VERSION 5.4 ;
NAMESCASESENSITIVE ON ;
BUSBITCHARS "[]" ;
DIVIDERCHAR "/" ;
UNITS
  DATABASE MICRONS 2000 ;
END UNITS
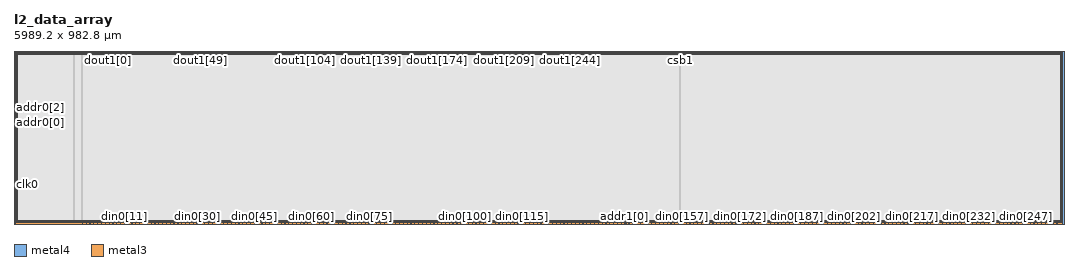
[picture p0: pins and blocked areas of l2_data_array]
MACRO l2_data_array
   CLASS BLOCK ;
   SIZE 5989.2 BY 982.8 ;
   SYMMETRY X Y R90 ;
   PIN din0[0]
      DIRECTION INPUT ;
      PORT
         LAYER metal4 ;
         RECT  389.4 0.0 390.6 1.2 ;
      END
   END din0[0]
   PIN din0[1]
      DIRECTION INPUT ;
      PORT
         LAYER metal4 ;
         RECT  411.2 0.0 412.4 1.2 ;
      END
   END din0[1]
   PIN din0[2]
      DIRECTION INPUT ;
      PORT
         LAYER metal4 ;
         RECT  433.0 0.0 434.2 1.2 ;
      END
   END din0[2]
   PIN din0[3]
      DIRECTION INPUT ;
      PORT
         LAYER metal4 ;
         RECT  454.8 0.0 456.0 1.2 ;
      END
   END din0[3]
   PIN din0[4]
      DIRECTION INPUT ;
      PORT
         LAYER metal4 ;
         RECT  476.6 0.0 477.8 1.2 ;
      END
   END din0[4]
   PIN din0[5]
      DIRECTION INPUT ;
      PORT
         LAYER metal4 ;
         RECT  498.4 0.0 499.6 1.2 ;
      END
   END din0[5]
   PIN din0[6]
      DIRECTION INPUT ;
      PORT
         LAYER metal4 ;
         RECT  520.2 0.0 521.4 1.2 ;
      END
   END din0[6]
   PIN din0[7]
      DIRECTION INPUT ;
      PORT
         LAYER metal4 ;
         RECT  542.0 0.0 543.2 1.2 ;
      END
   END din0[7]
   PIN din0[8]
      DIRECTION INPUT ;
      PORT
         LAYER metal4 ;
         RECT  563.8 0.0 565.0 1.2 ;
      END
   END din0[8]
   PIN din0[9]
      DIRECTION INPUT ;
      PORT
         LAYER metal4 ;
         RECT  585.6 0.0 586.8 1.2 ;
      END
   END din0[9]
   PIN din0[10]
      DIRECTION INPUT ;
      PORT
         LAYER metal4 ;
         RECT  607.4 0.0 608.6 1.2 ;
      END
   END din0[10]
   PIN din0[11]
      DIRECTION INPUT ;
      PORT
         LAYER metal4 ;
         RECT  629.2 0.0 630.4 1.2 ;
      END
   END din0[11]
   PIN din0[12]
      DIRECTION INPUT ;
      PORT
         LAYER metal4 ;
         RECT  651.0 0.0 652.2 1.2 ;
      END
   END din0[12]
   PIN din0[13]
      DIRECTION INPUT ;
      PORT
         LAYER metal4 ;
         RECT  672.8 0.0 674.0 1.2 ;
      END
   END din0[13]
   PIN din0[14]
      DIRECTION INPUT ;
      PORT
         LAYER metal4 ;
         RECT  694.6 0.0 695.8 1.2 ;
      END
   END din0[14]
   PIN din0[15]
      DIRECTION INPUT ;
      PORT
         LAYER metal4 ;
         RECT  716.4 0.0 717.6 1.2 ;
      END
   END din0[15]
   PIN din0[16]
      DIRECTION INPUT ;
      PORT
         LAYER metal4 ;
         RECT  738.2 0.0 739.4 1.2 ;
      END
   END din0[16]
   PIN din0[17]
      DIRECTION INPUT ;
      PORT
         LAYER metal4 ;
         RECT  760.0 0.0 761.2 1.2 ;
      END
   END din0[17]
   PIN din0[18]
      DIRECTION INPUT ;
      PORT
         LAYER metal4 ;
         RECT  781.8 0.0 783.0 1.2 ;
      END
   END din0[18]
   PIN din0[19]
      DIRECTION INPUT ;
      PORT
         LAYER metal4 ;
         RECT  803.6 0.0 804.8 1.2 ;
      END
   END din0[19]
   PIN din0[20]
      DIRECTION INPUT ;
      PORT
         LAYER metal4 ;
         RECT  825.4 0.0 826.6 1.2 ;
      END
   END din0[20]
   PIN din0[21]
      DIRECTION INPUT ;
      PORT
         LAYER metal4 ;
         RECT  847.2 0.0 848.4 1.2 ;
      END
   END din0[21]
   PIN din0[22]
      DIRECTION INPUT ;
      PORT
         LAYER metal4 ;
         RECT  869.0 0.0 870.2 1.2 ;
      END
   END din0[22]
   PIN din0[23]
      DIRECTION INPUT ;
      PORT
         LAYER metal4 ;
         RECT  890.8 0.0 892.0 1.2 ;
      END
   END din0[23]
   PIN din0[24]
      DIRECTION INPUT ;
      PORT
         LAYER metal4 ;
         RECT  912.6 0.0 913.8 1.2 ;
      END
   END din0[24]
   PIN din0[25]
      DIRECTION INPUT ;
      PORT
         LAYER metal4 ;
         RECT  934.4 0.0 935.6 1.2 ;
      END
   END din0[25]
   PIN din0[26]
      DIRECTION INPUT ;
      PORT
         LAYER metal4 ;
         RECT  956.2 0.0 957.4 1.2 ;
      END
   END din0[26]
   PIN din0[27]
      DIRECTION INPUT ;
      PORT
         LAYER metal4 ;
         RECT  978.0 0.0 979.2 1.2 ;
      END
   END din0[27]
   PIN din0[28]
      DIRECTION INPUT ;
      PORT
         LAYER metal4 ;
         RECT  999.8 0.0 1001.0 1.2 ;
      END
   END din0[28]
   PIN din0[29]
      DIRECTION INPUT ;
      PORT
         LAYER metal4 ;
         RECT  1021.6 0.0 1022.8 1.2 ;
      END
   END din0[29]
   PIN din0[30]
      DIRECTION INPUT ;
      PORT
         LAYER metal4 ;
         RECT  1043.4 0.0 1044.6 1.2 ;
      END
   END din0[30]
   PIN din0[31]
      DIRECTION INPUT ;
      PORT
         LAYER metal4 ;
         RECT  1065.2 0.0 1066.4 1.2 ;
      END
   END din0[31]
   PIN din0[32]
      DIRECTION INPUT ;
      PORT
         LAYER metal4 ;
         RECT  1087.0 0.0 1088.2 1.2 ;
      END
   END din0[32]
   PIN din0[33]
      DIRECTION INPUT ;
      PORT
         LAYER metal4 ;
         RECT  1108.8 0.0 1110.0 1.2 ;
      END
   END din0[33]
   PIN din0[34]
      DIRECTION INPUT ;
      PORT
         LAYER metal4 ;
         RECT  1130.6 0.0 1131.8 1.2 ;
      END
   END din0[34]
   PIN din0[35]
      DIRECTION INPUT ;
      PORT
         LAYER metal4 ;
         RECT  1152.4 0.0 1153.6 1.2 ;
      END
   END din0[35]
   PIN din0[36]
      DIRECTION INPUT ;
      PORT
         LAYER metal4 ;
         RECT  1174.2 0.0 1175.4 1.2 ;
      END
   END din0[36]
   PIN din0[37]
      DIRECTION INPUT ;
      PORT
         LAYER metal4 ;
         RECT  1196.0 0.0 1197.2 1.2 ;
      END
   END din0[37]
   PIN din0[38]
      DIRECTION INPUT ;
      PORT
         LAYER metal4 ;
         RECT  1217.8 0.0 1219.0 1.2 ;
      END
   END din0[38]
   PIN din0[39]
      DIRECTION INPUT ;
      PORT
         LAYER metal4 ;
         RECT  1239.6 0.0 1240.8 1.2 ;
      END
   END din0[39]
   PIN din0[40]
      DIRECTION INPUT ;
      PORT
         LAYER metal4 ;
         RECT  1261.4 0.0 1262.6 1.2 ;
      END
   END din0[40]
   PIN din0[41]
      DIRECTION INPUT ;
      PORT
         LAYER metal4 ;
         RECT  1283.2 0.0 1284.4 1.2 ;
      END
   END din0[41]
   PIN din0[42]
      DIRECTION INPUT ;
      PORT
         LAYER metal4 ;
         RECT  1305.0 0.0 1306.2 1.2 ;
      END
   END din0[42]
   PIN din0[43]
      DIRECTION INPUT ;
      PORT
         LAYER metal4 ;
         RECT  1326.8 0.0 1328.0 1.2 ;
      END
   END din0[43]
   PIN din0[44]
      DIRECTION INPUT ;
      PORT
         LAYER metal4 ;
         RECT  1348.6 0.0 1349.8 1.2 ;
      END
   END din0[44]
   PIN din0[45]
      DIRECTION INPUT ;
      PORT
         LAYER metal4 ;
         RECT  1370.4 0.0 1371.6 1.2 ;
      END
   END din0[45]
   PIN din0[46]
      DIRECTION INPUT ;
      PORT
         LAYER metal4 ;
         RECT  1392.2 0.0 1393.4 1.2 ;
      END
   END din0[46]
   PIN din0[47]
      DIRECTION INPUT ;
      PORT
         LAYER metal4 ;
         RECT  1414.0 0.0 1415.2 1.2 ;
      END
   END din0[47]
   PIN din0[48]
      DIRECTION INPUT ;
      PORT
         LAYER metal4 ;
         RECT  1435.8 0.0 1437.0 1.2 ;
      END
   END din0[48]
   PIN din0[49]
      DIRECTION INPUT ;
      PORT
         LAYER metal4 ;
         RECT  1457.6 0.0 1458.8 1.2 ;
      END
   END din0[49]
   PIN din0[50]
      DIRECTION INPUT ;
      PORT
         LAYER metal4 ;
         RECT  1479.4 0.0 1480.6 1.2 ;
      END
   END din0[50]
   PIN din0[51]
      DIRECTION INPUT ;
      PORT
         LAYER metal4 ;
         RECT  1501.2 0.0 1502.4 1.2 ;
      END
   END din0[51]
   PIN din0[52]
      DIRECTION INPUT ;
      PORT
         LAYER metal4 ;
         RECT  1523.0 0.0 1524.2 1.2 ;
      END
   END din0[52]
   PIN din0[53]
      DIRECTION INPUT ;
      PORT
         LAYER metal4 ;
         RECT  1544.8 0.0 1546.0 1.2 ;
      END
   END din0[53]
   PIN din0[54]
      DIRECTION INPUT ;
      PORT
         LAYER metal4 ;
         RECT  1566.6 0.0 1567.8 1.2 ;
      END
   END din0[54]
   PIN din0[55]
      DIRECTION INPUT ;
      PORT
         LAYER metal4 ;
         RECT  1588.4 0.0 1589.6 1.2 ;
      END
   END din0[55]
   PIN din0[56]
      DIRECTION INPUT ;
      PORT
         LAYER metal4 ;
         RECT  1610.2 0.0 1611.4 1.2 ;
      END
   END din0[56]
   PIN din0[57]
      DIRECTION INPUT ;
      PORT
         LAYER metal4 ;
         RECT  1632.0 0.0 1633.2 1.2 ;
      END
   END din0[57]
   PIN din0[58]
      DIRECTION INPUT ;
      PORT
         LAYER metal4 ;
         RECT  1653.8 0.0 1655.0 1.2 ;
      END
   END din0[58]
   PIN din0[59]
      DIRECTION INPUT ;
      PORT
         LAYER metal4 ;
         RECT  1675.6 0.0 1676.8 1.2 ;
      END
   END din0[59]
   PIN din0[60]
      DIRECTION INPUT ;
      PORT
         LAYER metal4 ;
         RECT  1697.4 0.0 1698.6 1.2 ;
      END
   END din0[60]
   PIN din0[61]
      DIRECTION INPUT ;
      PORT
         LAYER metal4 ;
         RECT  1719.2 0.0 1720.4 1.2 ;
      END
   END din0[61]
   PIN din0[62]
      DIRECTION INPUT ;
      PORT
         LAYER metal4 ;
         RECT  1741.0 0.0 1742.2 1.2 ;
      END
   END din0[62]
   PIN din0[63]
      DIRECTION INPUT ;
      PORT
         LAYER metal4 ;
         RECT  1762.8 0.0 1764.0 1.2 ;
      END
   END din0[63]
   PIN din0[64]
      DIRECTION INPUT ;
      PORT
         LAYER metal4 ;
         RECT  1784.6 0.0 1785.8 1.2 ;
      END
   END din0[64]
   PIN din0[65]
      DIRECTION INPUT ;
      PORT
         LAYER metal4 ;
         RECT  1806.4 0.0 1807.6 1.2 ;
      END
   END din0[65]
   PIN din0[66]
      DIRECTION INPUT ;
      PORT
         LAYER metal4 ;
         RECT  1828.2 0.0 1829.4 1.2 ;
      END
   END din0[66]
   PIN din0[67]
      DIRECTION INPUT ;
      PORT
         LAYER metal4 ;
         RECT  1850.0 0.0 1851.2 1.2 ;
      END
   END din0[67]
   PIN din0[68]
      DIRECTION INPUT ;
      PORT
         LAYER metal4 ;
         RECT  1871.8 0.0 1873.0 1.2 ;
      END
   END din0[68]
   PIN din0[69]
      DIRECTION INPUT ;
      PORT
         LAYER metal4 ;
         RECT  1893.6 0.0 1894.8 1.2 ;
      END
   END din0[69]
   PIN din0[70]
      DIRECTION INPUT ;
      PORT
         LAYER metal4 ;
         RECT  1915.4 0.0 1916.6 1.2 ;
      END
   END din0[70]
   PIN din0[71]
      DIRECTION INPUT ;
      PORT
         LAYER metal4 ;
         RECT  1937.2 0.0 1938.4 1.2 ;
      END
   END din0[71]
   PIN din0[72]
      DIRECTION INPUT ;
      PORT
         LAYER metal4 ;
         RECT  1959.0 0.0 1960.2 1.2 ;
      END
   END din0[72]
   PIN din0[73]
      DIRECTION INPUT ;
      PORT
         LAYER metal4 ;
         RECT  1980.8 0.0 1982.0 1.2 ;
      END
   END din0[73]
   PIN din0[74]
      DIRECTION INPUT ;
      PORT
         LAYER metal4 ;
         RECT  2002.6 0.0 2003.8 1.2 ;
      END
   END din0[74]
   PIN din0[75]
      DIRECTION INPUT ;
      PORT
         LAYER metal4 ;
         RECT  2024.4 0.0 2025.6 1.2 ;
      END
   END din0[75]
   PIN din0[76]
      DIRECTION INPUT ;
      PORT
         LAYER metal4 ;
         RECT  2046.2 0.0 2047.4 1.2 ;
      END
   END din0[76]
   PIN din0[77]
      DIRECTION INPUT ;
      PORT
         LAYER metal4 ;
         RECT  2068.0 0.0 2069.2 1.2 ;
      END
   END din0[77]
   PIN din0[78]
      DIRECTION INPUT ;
      PORT
         LAYER metal4 ;
         RECT  2089.8 0.0 2091.0 1.2 ;
      END
   END din0[78]
   PIN din0[79]
      DIRECTION INPUT ;
      PORT
         LAYER metal4 ;
         RECT  2111.6 0.0 2112.8 1.2 ;
      END
   END din0[79]
   PIN din0[80]
      DIRECTION INPUT ;
      PORT
         LAYER metal4 ;
         RECT  2133.4 0.0 2134.6 1.2 ;
      END
   END din0[80]
   PIN din0[81]
      DIRECTION INPUT ;
      PORT
         LAYER metal4 ;
         RECT  2155.2 0.0 2156.4 1.2 ;
      END
   END din0[81]
   PIN din0[82]
      DIRECTION INPUT ;
      PORT
         LAYER metal4 ;
         RECT  2177.0 0.0 2178.2 1.2 ;
      END
   END din0[82]
   PIN din0[83]
      DIRECTION INPUT ;
      PORT
         LAYER metal4 ;
         RECT  2198.8 0.0 2200.0 1.2 ;
      END
   END din0[83]
   PIN din0[84]
      DIRECTION INPUT ;
      PORT
         LAYER metal4 ;
         RECT  2220.6 0.0 2221.8 1.2 ;
      END
   END din0[84]
   PIN din0[85]
      DIRECTION INPUT ;
      PORT
         LAYER metal4 ;
         RECT  2242.4 0.0 2243.6 1.2 ;
      END
   END din0[85]
   PIN din0[86]
      DIRECTION INPUT ;
      PORT
         LAYER metal4 ;
         RECT  2264.2 0.0 2265.4 1.2 ;
      END
   END din0[86]
   PIN din0[87]
      DIRECTION INPUT ;
      PORT
         LAYER metal4 ;
         RECT  2286.0 0.0 2287.2 1.2 ;
      END
   END din0[87]
   PIN din0[88]
      DIRECTION INPUT ;
      PORT
         LAYER metal4 ;
         RECT  2307.8 0.0 2309.0 1.2 ;
      END
   END din0[88]
   PIN din0[89]
      DIRECTION INPUT ;
      PORT
         LAYER metal4 ;
         RECT  2329.6 0.0 2330.8 1.2 ;
      END
   END din0[89]
   PIN din0[90]
      DIRECTION INPUT ;
      PORT
         LAYER metal4 ;
         RECT  2351.4 0.0 2352.6 1.2 ;
      END
   END din0[90]
   PIN din0[91]
      DIRECTION INPUT ;
      PORT
         LAYER metal4 ;
         RECT  2373.2 0.0 2374.4 1.2 ;
      END
   END din0[91]
   PIN din0[92]
      DIRECTION INPUT ;
      PORT
         LAYER metal4 ;
         RECT  2395.0 0.0 2396.2 1.2 ;
      END
   END din0[92]
   PIN din0[93]
      DIRECTION INPUT ;
      PORT
         LAYER metal4 ;
         RECT  2416.8 0.0 2418.0 1.2 ;
      END
   END din0[93]
   PIN din0[94]
      DIRECTION INPUT ;
      PORT
         LAYER metal4 ;
         RECT  2438.6 0.0 2439.8 1.2 ;
      END
   END din0[94]
   PIN din0[95]
      DIRECTION INPUT ;
      PORT
         LAYER metal4 ;
         RECT  2460.4 0.0 2461.6 1.2 ;
      END
   END din0[95]
   PIN din0[96]
      DIRECTION INPUT ;
      PORT
         LAYER metal4 ;
         RECT  2482.2 0.0 2483.4 1.2 ;
      END
   END din0[96]
   PIN din0[97]
      DIRECTION INPUT ;
      PORT
         LAYER metal4 ;
         RECT  2504.0 0.0 2505.2 1.2 ;
      END
   END din0[97]
   PIN din0[98]
      DIRECTION INPUT ;
      PORT
         LAYER metal4 ;
         RECT  2525.8 0.0 2527.0 1.2 ;
      END
   END din0[98]
   PIN din0[99]
      DIRECTION INPUT ;
      PORT
         LAYER metal4 ;
         RECT  2547.6 0.0 2548.8 1.2 ;
      END
   END din0[99]
   PIN din0[100]
      DIRECTION INPUT ;
      PORT
         LAYER metal4 ;
         RECT  2569.4 0.0 2570.6 1.2 ;
      END
   END din0[100]
   PIN din0[101]
      DIRECTION INPUT ;
      PORT
         LAYER metal4 ;
         RECT  2591.2 0.0 2592.4 1.2 ;
      END
   END din0[101]
   PIN din0[102]
      DIRECTION INPUT ;
      PORT
         LAYER metal4 ;
         RECT  2613.0 0.0 2614.2 1.2 ;
      END
   END din0[102]
   PIN din0[103]
      DIRECTION INPUT ;
      PORT
         LAYER metal4 ;
         RECT  2634.8 0.0 2636.0 1.2 ;
      END
   END din0[103]
   PIN din0[104]
      DIRECTION INPUT ;
      PORT
         LAYER metal4 ;
         RECT  2656.6 0.0 2657.8 1.2 ;
      END
   END din0[104]
   PIN din0[105]
      DIRECTION INPUT ;
      PORT
         LAYER metal4 ;
         RECT  2678.4 0.0 2679.6 1.2 ;
      END
   END din0[105]
   PIN din0[106]
      DIRECTION INPUT ;
      PORT
         LAYER metal4 ;
         RECT  2700.2 0.0 2701.4 1.2 ;
      END
   END din0[106]
   PIN din0[107]
      DIRECTION INPUT ;
      PORT
         LAYER metal4 ;
         RECT  2722.0 0.0 2723.2 1.2 ;
      END
   END din0[107]
   PIN din0[108]
      DIRECTION INPUT ;
      PORT
         LAYER metal4 ;
         RECT  2743.8 0.0 2745.0 1.2 ;
      END
   END din0[108]
   PIN din0[109]
      DIRECTION INPUT ;
      PORT
         LAYER metal4 ;
         RECT  2765.6 0.0 2766.8 1.2 ;
      END
   END din0[109]
   PIN din0[110]
      DIRECTION INPUT ;
      PORT
         LAYER metal4 ;
         RECT  2787.4 0.0 2788.6 1.2 ;
      END
   END din0[110]
   PIN din0[111]
      DIRECTION INPUT ;
      PORT
         LAYER metal4 ;
         RECT  2809.2 0.0 2810.4 1.2 ;
      END
   END din0[111]
   PIN din0[112]
      DIRECTION INPUT ;
      PORT
         LAYER metal4 ;
         RECT  2831.0 0.0 2832.2 1.2 ;
      END
   END din0[112]
   PIN din0[113]
      DIRECTION INPUT ;
      PORT
         LAYER metal4 ;
         RECT  2852.8 0.0 2854.0 1.2 ;
      END
   END din0[113]
   PIN din0[114]
      DIRECTION INPUT ;
      PORT
         LAYER metal4 ;
         RECT  2874.6 0.0 2875.8 1.2 ;
      END
   END din0[114]
   PIN din0[115]
      DIRECTION INPUT ;
      PORT
         LAYER metal4 ;
         RECT  2896.4 0.0 2897.6 1.2 ;
      END
   END din0[115]
   PIN din0[116]
      DIRECTION INPUT ;
      PORT
         LAYER metal4 ;
         RECT  2918.2 0.0 2919.4 1.2 ;
      END
   END din0[116]
   PIN din0[117]
      DIRECTION INPUT ;
      PORT
         LAYER metal4 ;
         RECT  2940.0 0.0 2941.2 1.2 ;
      END
   END din0[117]
   PIN din0[118]
      DIRECTION INPUT ;
      PORT
         LAYER metal4 ;
         RECT  2961.8 0.0 2963.0 1.2 ;
      END
   END din0[118]
   PIN din0[119]
      DIRECTION INPUT ;
      PORT
         LAYER metal4 ;
         RECT  2983.6 0.0 2984.8 1.2 ;
      END
   END din0[119]
   PIN din0[120]
      DIRECTION INPUT ;
      PORT
         LAYER metal4 ;
         RECT  3005.4 0.0 3006.6 1.2 ;
      END
   END din0[120]
   PIN din0[121]
      DIRECTION INPUT ;
      PORT
         LAYER metal4 ;
         RECT  3027.2 0.0 3028.4 1.2 ;
      END
   END din0[121]
   PIN din0[122]
      DIRECTION INPUT ;
      PORT
         LAYER metal4 ;
         RECT  3049.0 0.0 3050.2 1.2 ;
      END
   END din0[122]
   PIN din0[123]
      DIRECTION INPUT ;
      PORT
         LAYER metal4 ;
         RECT  3070.8 0.0 3072.0 1.2 ;
      END
   END din0[123]
   PIN din0[124]
      DIRECTION INPUT ;
      PORT
         LAYER metal4 ;
         RECT  3092.6 0.0 3093.8 1.2 ;
      END
   END din0[124]
   PIN din0[125]
      DIRECTION INPUT ;
      PORT
         LAYER metal4 ;
         RECT  3114.4 0.0 3115.6 1.2 ;
      END
   END din0[125]
   PIN din0[126]
      DIRECTION INPUT ;
      PORT
         LAYER metal4 ;
         RECT  3136.2 0.0 3137.4 1.2 ;
      END
   END din0[126]
   PIN din0[127]
      DIRECTION INPUT ;
      PORT
         LAYER metal4 ;
         RECT  3158.0 0.0 3159.2 1.2 ;
      END
   END din0[127]
   PIN din0[128]
      DIRECTION INPUT ;
      PORT
         LAYER metal4 ;
         RECT  3179.8 0.0 3181.0 1.2 ;
      END
   END din0[128]
   PIN din0[129]
      DIRECTION INPUT ;
      PORT
         LAYER metal4 ;
         RECT  3201.6 0.0 3202.8 1.2 ;
      END
   END din0[129]
   PIN din0[130]
      DIRECTION INPUT ;
      PORT
         LAYER metal4 ;
         RECT  3223.4 0.0 3224.6 1.2 ;
      END
   END din0[130]
   PIN din0[131]
      DIRECTION INPUT ;
      PORT
         LAYER metal4 ;
         RECT  3245.2 0.0 3246.4 1.2 ;
      END
   END din0[131]
   PIN din0[132]
      DIRECTION INPUT ;
      PORT
         LAYER metal4 ;
         RECT  3267.0 0.0 3268.2 1.2 ;
      END
   END din0[132]
   PIN din0[133]
      DIRECTION INPUT ;
      PORT
         LAYER metal4 ;
         RECT  3288.8 0.0 3290.0 1.2 ;
      END
   END din0[133]
   PIN din0[134]
      DIRECTION INPUT ;
      PORT
         LAYER metal4 ;
         RECT  3310.6 0.0 3311.8 1.2 ;
      END
   END din0[134]
   PIN din0[135]
      DIRECTION INPUT ;
      PORT
         LAYER metal4 ;
         RECT  3332.4 0.0 3333.6 1.2 ;
      END
   END din0[135]
   PIN din0[136]
      DIRECTION INPUT ;
      PORT
         LAYER metal4 ;
         RECT  3354.2 0.0 3355.4 1.2 ;
      END
   END din0[136]
   PIN din0[137]
      DIRECTION INPUT ;
      PORT
         LAYER metal4 ;
         RECT  3376.0 0.0 3377.2 1.2 ;
      END
   END din0[137]
   PIN din0[138]
      DIRECTION INPUT ;
      PORT
         LAYER metal4 ;
         RECT  3397.8 0.0 3399.0 1.2 ;
      END
   END din0[138]
   PIN din0[139]
      DIRECTION INPUT ;
      PORT
         LAYER metal4 ;
         RECT  3419.6 0.0 3420.8 1.2 ;
      END
   END din0[139]
   PIN din0[140]
      DIRECTION INPUT ;
      PORT
         LAYER metal4 ;
         RECT  3441.4 0.0 3442.6 1.2 ;
      END
   END din0[140]
   PIN din0[141]
      DIRECTION INPUT ;
      PORT
         LAYER metal4 ;
         RECT  3463.2 0.0 3464.4 1.2 ;
      END
   END din0[141]
   PIN din0[142]
      DIRECTION INPUT ;
      PORT
         LAYER metal4 ;
         RECT  3485.0 0.0 3486.2 1.2 ;
      END
   END din0[142]
   PIN din0[143]
      DIRECTION INPUT ;
      PORT
         LAYER metal4 ;
         RECT  3506.8 0.0 3508.0 1.2 ;
      END
   END din0[143]
   PIN din0[144]
      DIRECTION INPUT ;
      PORT
         LAYER metal4 ;
         RECT  3528.6 0.0 3529.8 1.2 ;
      END
   END din0[144]
   PIN din0[145]
      DIRECTION INPUT ;
      PORT
         LAYER metal4 ;
         RECT  3550.4 0.0 3551.6 1.2 ;
      END
   END din0[145]
   PIN din0[146]
      DIRECTION INPUT ;
      PORT
         LAYER metal4 ;
         RECT  3572.2 0.0 3573.4 1.2 ;
      END
   END din0[146]
   PIN din0[147]
      DIRECTION INPUT ;
      PORT
         LAYER metal4 ;
         RECT  3594.0 0.0 3595.2 1.2 ;
      END
   END din0[147]
   PIN din0[148]
      DIRECTION INPUT ;
      PORT
         LAYER metal4 ;
         RECT  3615.8 0.0 3617.0 1.2 ;
      END
   END din0[148]
   PIN din0[149]
      DIRECTION INPUT ;
      PORT
         LAYER metal4 ;
         RECT  3637.6 0.0 3638.8 1.2 ;
      END
   END din0[149]
   PIN din0[150]
      DIRECTION INPUT ;
      PORT
         LAYER metal4 ;
         RECT  3659.4 0.0 3660.6 1.2 ;
      END
   END din0[150]
   PIN din0[151]
      DIRECTION INPUT ;
      PORT
         LAYER metal4 ;
         RECT  3681.2 0.0 3682.4 1.2 ;
      END
   END din0[151]
   PIN din0[152]
      DIRECTION INPUT ;
      PORT
         LAYER metal4 ;
         RECT  3703.0 0.0 3704.2 1.2 ;
      END
   END din0[152]
   PIN din0[153]
      DIRECTION INPUT ;
      PORT
         LAYER metal4 ;
         RECT  3724.8 0.0 3726.0 1.2 ;
      END
   END din0[153]
   PIN din0[154]
      DIRECTION INPUT ;
      PORT
         LAYER metal4 ;
         RECT  3746.6 0.0 3747.8 1.2 ;
      END
   END din0[154]
   PIN din0[155]
      DIRECTION INPUT ;
      PORT
         LAYER metal4 ;
         RECT  3768.4 0.0 3769.6 1.2 ;
      END
   END din0[155]
   PIN din0[156]
      DIRECTION INPUT ;
      PORT
         LAYER metal4 ;
         RECT  3790.2 0.0 3791.4 1.2 ;
      END
   END din0[156]
   PIN din0[157]
      DIRECTION INPUT ;
      PORT
         LAYER metal4 ;
         RECT  3812.0 0.0 3813.2 1.2 ;
      END
   END din0[157]
   PIN din0[158]
      DIRECTION INPUT ;
      PORT
         LAYER metal4 ;
         RECT  3833.8 0.0 3835.0 1.2 ;
      END
   END din0[158]
   PIN din0[159]
      DIRECTION INPUT ;
      PORT
         LAYER metal4 ;
         RECT  3855.6 0.0 3856.8 1.2 ;
      END
   END din0[159]
   PIN din0[160]
      DIRECTION INPUT ;
      PORT
         LAYER metal4 ;
         RECT  3877.4 0.0 3878.6 1.2 ;
      END
   END din0[160]
   PIN din0[161]
      DIRECTION INPUT ;
      PORT
         LAYER metal4 ;
         RECT  3899.2 0.0 3900.4 1.2 ;
      END
   END din0[161]
   PIN din0[162]
      DIRECTION INPUT ;
      PORT
         LAYER metal4 ;
         RECT  3921.0 0.0 3922.2 1.2 ;
      END
   END din0[162]
   PIN din0[163]
      DIRECTION INPUT ;
      PORT
         LAYER metal4 ;
         RECT  3942.8 0.0 3944.0 1.2 ;
      END
   END din0[163]
   PIN din0[164]
      DIRECTION INPUT ;
      PORT
         LAYER metal4 ;
         RECT  3964.6 0.0 3965.8 1.2 ;
      END
   END din0[164]
   PIN din0[165]
      DIRECTION INPUT ;
      PORT
         LAYER metal4 ;
         RECT  3986.4 0.0 3987.6 1.2 ;
      END
   END din0[165]
   PIN din0[166]
      DIRECTION INPUT ;
      PORT
         LAYER metal4 ;
         RECT  4008.2 0.0 4009.4 1.2 ;
      END
   END din0[166]
   PIN din0[167]
      DIRECTION INPUT ;
      PORT
         LAYER metal4 ;
         RECT  4030.0 0.0 4031.2 1.2 ;
      END
   END din0[167]
   PIN din0[168]
      DIRECTION INPUT ;
      PORT
         LAYER metal4 ;
         RECT  4051.8 0.0 4053.0 1.2 ;
      END
   END din0[168]
   PIN din0[169]
      DIRECTION INPUT ;
      PORT
         LAYER metal4 ;
         RECT  4073.6 0.0 4074.8 1.2 ;
      END
   END din0[169]
   PIN din0[170]
      DIRECTION INPUT ;
      PORT
         LAYER metal4 ;
         RECT  4095.4 0.0 4096.6 1.2 ;
      END
   END din0[170]
   PIN din0[171]
      DIRECTION INPUT ;
      PORT
         LAYER metal4 ;
         RECT  4117.2 0.0 4118.4 1.2 ;
      END
   END din0[171]
   PIN din0[172]
      DIRECTION INPUT ;
      PORT
         LAYER metal4 ;
         RECT  4139.0 0.0 4140.2 1.2 ;
      END
   END din0[172]
   PIN din0[173]
      DIRECTION INPUT ;
      PORT
         LAYER metal4 ;
         RECT  4160.8 0.0 4162.0 1.2 ;
      END
   END din0[173]
   PIN din0[174]
      DIRECTION INPUT ;
      PORT
         LAYER metal4 ;
         RECT  4182.6 0.0 4183.8 1.2 ;
      END
   END din0[174]
   PIN din0[175]
      DIRECTION INPUT ;
      PORT
         LAYER metal4 ;
         RECT  4204.4 0.0 4205.6 1.2 ;
      END
   END din0[175]
   PIN din0[176]
      DIRECTION INPUT ;
      PORT
         LAYER metal4 ;
         RECT  4226.2 0.0 4227.4 1.2 ;
      END
   END din0[176]
   PIN din0[177]
      DIRECTION INPUT ;
      PORT
         LAYER metal4 ;
         RECT  4248.0 0.0 4249.2 1.2 ;
      END
   END din0[177]
   PIN din0[178]
      DIRECTION INPUT ;
      PORT
         LAYER metal4 ;
         RECT  4269.8 0.0 4271.0 1.2 ;
      END
   END din0[178]
   PIN din0[179]
      DIRECTION INPUT ;
      PORT
         LAYER metal4 ;
         RECT  4291.6 0.0 4292.8 1.2 ;
      END
   END din0[179]
   PIN din0[180]
      DIRECTION INPUT ;
      PORT
         LAYER metal4 ;
         RECT  4313.4 0.0 4314.6 1.2 ;
      END
   END din0[180]
   PIN din0[181]
      DIRECTION INPUT ;
      PORT
         LAYER metal4 ;
         RECT  4335.2 0.0 4336.4 1.2 ;
      END
   END din0[181]
   PIN din0[182]
      DIRECTION INPUT ;
      PORT
         LAYER metal4 ;
         RECT  4357.0 0.0 4358.2 1.2 ;
      END
   END din0[182]
   PIN din0[183]
      DIRECTION INPUT ;
      PORT
         LAYER metal4 ;
         RECT  4378.8 0.0 4380.0 1.2 ;
      END
   END din0[183]
   PIN din0[184]
      DIRECTION INPUT ;
      PORT
         LAYER metal4 ;
         RECT  4400.6 0.0 4401.8 1.2 ;
      END
   END din0[184]
   PIN din0[185]
      DIRECTION INPUT ;
      PORT
         LAYER metal4 ;
         RECT  4422.4 0.0 4423.6 1.2 ;
      END
   END din0[185]
   PIN din0[186]
      DIRECTION INPUT ;
      PORT
         LAYER metal4 ;
         RECT  4444.2 0.0 4445.4 1.2 ;
      END
   END din0[186]
   PIN din0[187]
      DIRECTION INPUT ;
      PORT
         LAYER metal4 ;
         RECT  4466.0 0.0 4467.2 1.2 ;
      END
   END din0[187]
   PIN din0[188]
      DIRECTION INPUT ;
      PORT
         LAYER metal4 ;
         RECT  4487.8 0.0 4489.0 1.2 ;
      END
   END din0[188]
   PIN din0[189]
      DIRECTION INPUT ;
      PORT
         LAYER metal4 ;
         RECT  4509.6 0.0 4510.8 1.2 ;
      END
   END din0[189]
   PIN din0[190]
      DIRECTION INPUT ;
      PORT
         LAYER metal4 ;
         RECT  4531.4 0.0 4532.6 1.2 ;
      END
   END din0[190]
   PIN din0[191]
      DIRECTION INPUT ;
      PORT
         LAYER metal4 ;
         RECT  4553.2 0.0 4554.4 1.2 ;
      END
   END din0[191]
   PIN din0[192]
      DIRECTION INPUT ;
      PORT
         LAYER metal4 ;
         RECT  4575.0 0.0 4576.2 1.2 ;
      END
   END din0[192]
   PIN din0[193]
      DIRECTION INPUT ;
      PORT
         LAYER metal4 ;
         RECT  4596.8 0.0 4598.0 1.2 ;
      END
   END din0[193]
   PIN din0[194]
      DIRECTION INPUT ;
      PORT
         LAYER metal4 ;
         RECT  4618.6 0.0 4619.8 1.2 ;
      END
   END din0[194]
   PIN din0[195]
      DIRECTION INPUT ;
      PORT
         LAYER metal4 ;
         RECT  4640.4 0.0 4641.6 1.2 ;
      END
   END din0[195]
   PIN din0[196]
      DIRECTION INPUT ;
      PORT
         LAYER metal4 ;
         RECT  4662.2 0.0 4663.4 1.2 ;
      END
   END din0[196]
   PIN din0[197]
      DIRECTION INPUT ;
      PORT
         LAYER metal4 ;
         RECT  4684.0 0.0 4685.2 1.2 ;
      END
   END din0[197]
   PIN din0[198]
      DIRECTION INPUT ;
      PORT
         LAYER metal4 ;
         RECT  4705.8 0.0 4707.0 1.2 ;
      END
   END din0[198]
   PIN din0[199]
      DIRECTION INPUT ;
      PORT
         LAYER metal4 ;
         RECT  4727.6 0.0 4728.8 1.2 ;
      END
   END din0[199]
   PIN din0[200]
      DIRECTION INPUT ;
      PORT
         LAYER metal4 ;
         RECT  4749.4 0.0 4750.6 1.2 ;
      END
   END din0[200]
   PIN din0[201]
      DIRECTION INPUT ;
      PORT
         LAYER metal4 ;
         RECT  4771.2 0.0 4772.4 1.2 ;
      END
   END din0[201]
   PIN din0[202]
      DIRECTION INPUT ;
      PORT
         LAYER metal4 ;
         RECT  4793.0 0.0 4794.2 1.2 ;
      END
   END din0[202]
   PIN din0[203]
      DIRECTION INPUT ;
      PORT
         LAYER metal4 ;
         RECT  4814.8 0.0 4816.0 1.2 ;
      END
   END din0[203]
   PIN din0[204]
      DIRECTION INPUT ;
      PORT
         LAYER metal4 ;
         RECT  4836.6 0.0 4837.8 1.2 ;
      END
   END din0[204]
   PIN din0[205]
      DIRECTION INPUT ;
      PORT
         LAYER metal4 ;
         RECT  4858.4 0.0 4859.6 1.2 ;
      END
   END din0[205]
   PIN din0[206]
      DIRECTION INPUT ;
      PORT
         LAYER metal4 ;
         RECT  4880.2 0.0 4881.4 1.2 ;
      END
   END din0[206]
   PIN din0[207]
      DIRECTION INPUT ;
      PORT
         LAYER metal4 ;
         RECT  4902.0 0.0 4903.2 1.2 ;
      END
   END din0[207]
   PIN din0[208]
      DIRECTION INPUT ;
      PORT
         LAYER metal4 ;
         RECT  4923.8 0.0 4925.0 1.2 ;
      END
   END din0[208]
   PIN din0[209]
      DIRECTION INPUT ;
      PORT
         LAYER metal4 ;
         RECT  4945.6 0.0 4946.8 1.2 ;
      END
   END din0[209]
   PIN din0[210]
      DIRECTION INPUT ;
      PORT
         LAYER metal4 ;
         RECT  4967.4 0.0 4968.6 1.2 ;
      END
   END din0[210]
   PIN din0[211]
      DIRECTION INPUT ;
      PORT
         LAYER metal4 ;
         RECT  4989.2 0.0 4990.4 1.2 ;
      END
   END din0[211]
   PIN din0[212]
      DIRECTION INPUT ;
      PORT
         LAYER metal4 ;
         RECT  5011.0 0.0 5012.2 1.2 ;
      END
   END din0[212]
   PIN din0[213]
      DIRECTION INPUT ;
      PORT
         LAYER metal4 ;
         RECT  5032.8 0.0 5034.0 1.2 ;
      END
   END din0[213]
   PIN din0[214]
      DIRECTION INPUT ;
      PORT
         LAYER metal4 ;
         RECT  5054.6 0.0 5055.8 1.2 ;
      END
   END din0[214]
   PIN din0[215]
      DIRECTION INPUT ;
      PORT
         LAYER metal4 ;
         RECT  5076.4 0.0 5077.6 1.2 ;
      END
   END din0[215]
   PIN din0[216]
      DIRECTION INPUT ;
      PORT
         LAYER metal4 ;
         RECT  5098.2 0.0 5099.4 1.2 ;
      END
   END din0[216]
   PIN din0[217]
      DIRECTION INPUT ;
      PORT
         LAYER metal4 ;
         RECT  5120.0 0.0 5121.2 1.2 ;
      END
   END din0[217]
   PIN din0[218]
      DIRECTION INPUT ;
      PORT
         LAYER metal4 ;
         RECT  5141.8 0.0 5143.0 1.2 ;
      END
   END din0[218]
   PIN din0[219]
      DIRECTION INPUT ;
      PORT
         LAYER metal4 ;
         RECT  5163.6 0.0 5164.8 1.2 ;
      END
   END din0[219]
   PIN din0[220]
      DIRECTION INPUT ;
      PORT
         LAYER metal4 ;
         RECT  5185.4 0.0 5186.6 1.2 ;
      END
   END din0[220]
   PIN din0[221]
      DIRECTION INPUT ;
      PORT
         LAYER metal4 ;
         RECT  5207.2 0.0 5208.4 1.2 ;
      END
   END din0[221]
   PIN din0[222]
      DIRECTION INPUT ;
      PORT
         LAYER metal4 ;
         RECT  5229.0 0.0 5230.2 1.2 ;
      END
   END din0[222]
   PIN din0[223]
      DIRECTION INPUT ;
      PORT
         LAYER metal4 ;
         RECT  5250.8 0.0 5252.0 1.2 ;
      END
   END din0[223]
   PIN din0[224]
      DIRECTION INPUT ;
      PORT
         LAYER metal4 ;
         RECT  5272.6 0.0 5273.8 1.2 ;
      END
   END din0[224]
   PIN din0[225]
      DIRECTION INPUT ;
      PORT
         LAYER metal4 ;
         RECT  5294.4 0.0 5295.6 1.2 ;
      END
   END din0[225]
   PIN din0[226]
      DIRECTION INPUT ;
      PORT
         LAYER metal4 ;
         RECT  5316.2 0.0 5317.4 1.2 ;
      END
   END din0[226]
   PIN din0[227]
      DIRECTION INPUT ;
      PORT
         LAYER metal4 ;
         RECT  5338.0 0.0 5339.2 1.2 ;
      END
   END din0[227]
   PIN din0[228]
      DIRECTION INPUT ;
      PORT
         LAYER metal4 ;
         RECT  5359.8 0.0 5361.0 1.2 ;
      END
   END din0[228]
   PIN din0[229]
      DIRECTION INPUT ;
      PORT
         LAYER metal4 ;
         RECT  5381.6 0.0 5382.8 1.2 ;
      END
   END din0[229]
   PIN din0[230]
      DIRECTION INPUT ;
      PORT
         LAYER metal4 ;
         RECT  5403.4 0.0 5404.6 1.2 ;
      END
   END din0[230]
   PIN din0[231]
      DIRECTION INPUT ;
      PORT
         LAYER metal4 ;
         RECT  5425.2 0.0 5426.4 1.2 ;
      END
   END din0[231]
   PIN din0[232]
      DIRECTION INPUT ;
      PORT
         LAYER metal4 ;
         RECT  5447.0 0.0 5448.2 1.2 ;
      END
   END din0[232]
   PIN din0[233]
      DIRECTION INPUT ;
      PORT
         LAYER metal4 ;
         RECT  5468.8 0.0 5470.0 1.2 ;
      END
   END din0[233]
   PIN din0[234]
      DIRECTION INPUT ;
      PORT
         LAYER metal4 ;
         RECT  5490.6 0.0 5491.8 1.2 ;
      END
   END din0[234]
   PIN din0[235]
      DIRECTION INPUT ;
      PORT
         LAYER metal4 ;
         RECT  5512.4 0.0 5513.6 1.2 ;
      END
   END din0[235]
   PIN din0[236]
      DIRECTION INPUT ;
      PORT
         LAYER metal4 ;
         RECT  5534.2 0.0 5535.4 1.2 ;
      END
   END din0[236]
   PIN din0[237]
      DIRECTION INPUT ;
      PORT
         LAYER metal4 ;
         RECT  5556.0 0.0 5557.2 1.2 ;
      END
   END din0[237]
   PIN din0[238]
      DIRECTION INPUT ;
      PORT
         LAYER metal4 ;
         RECT  5577.8 0.0 5579.0 1.2 ;
      END
   END din0[238]
   PIN din0[239]
      DIRECTION INPUT ;
      PORT
         LAYER metal4 ;
         RECT  5599.6 0.0 5600.8 1.2 ;
      END
   END din0[239]
   PIN din0[240]
      DIRECTION INPUT ;
      PORT
         LAYER metal4 ;
         RECT  5621.4 0.0 5622.6 1.2 ;
      END
   END din0[240]
   PIN din0[241]
      DIRECTION INPUT ;
      PORT
         LAYER metal4 ;
         RECT  5643.2 0.0 5644.4 1.2 ;
      END
   END din0[241]
   PIN din0[242]
      DIRECTION INPUT ;
      PORT
         LAYER metal4 ;
         RECT  5665.0 0.0 5666.2 1.2 ;
      END
   END din0[242]
   PIN din0[243]
      DIRECTION INPUT ;
      PORT
         LAYER metal4 ;
         RECT  5686.8 0.0 5688.0 1.2 ;
      END
   END din0[243]
   PIN din0[244]
      DIRECTION INPUT ;
      PORT
         LAYER metal4 ;
         RECT  5708.6 0.0 5709.8 1.2 ;
      END
   END din0[244]
   PIN din0[245]
      DIRECTION INPUT ;
      PORT
         LAYER metal4 ;
         RECT  5730.4 0.0 5731.6 1.2 ;
      END
   END din0[245]
   PIN din0[246]
      DIRECTION INPUT ;
      PORT
         LAYER metal4 ;
         RECT  5752.2 0.0 5753.4 1.2 ;
      END
   END din0[246]
   PIN din0[247]
      DIRECTION INPUT ;
      PORT
         LAYER metal4 ;
         RECT  5774.0 0.0 5775.2 1.2 ;
      END
   END din0[247]
   PIN din0[248]
      DIRECTION INPUT ;
      PORT
         LAYER metal4 ;
         RECT  5795.8 0.0 5797.0 1.2 ;
      END
   END din0[248]
   PIN din0[249]
      DIRECTION INPUT ;
      PORT
         LAYER metal4 ;
         RECT  5817.6 0.0 5818.8 1.2 ;
      END
   END din0[249]
   PIN din0[250]
      DIRECTION INPUT ;
      PORT
         LAYER metal4 ;
         RECT  5839.4 0.0 5840.6 1.2 ;
      END
   END din0[250]
   PIN din0[251]
      DIRECTION INPUT ;
      PORT
         LAYER metal4 ;
         RECT  5861.2 0.0 5862.4 1.2 ;
      END
   END din0[251]
   PIN din0[252]
      DIRECTION INPUT ;
      PORT
         LAYER metal4 ;
         RECT  5883.0 0.0 5884.2 1.2 ;
      END
   END din0[252]
   PIN din0[253]
      DIRECTION INPUT ;
      PORT
         LAYER metal4 ;
         RECT  5904.8 0.0 5906.0 1.2 ;
      END
   END din0[253]
   PIN din0[254]
      DIRECTION INPUT ;
      PORT
         LAYER metal4 ;
         RECT  5926.6 0.0 5927.8 1.2 ;
      END
   END din0[254]
   PIN din0[255]
      DIRECTION INPUT ;
      PORT
         LAYER metal4 ;
         RECT  5948.4 0.0 5949.6 1.2 ;
      END
   END din0[255]
   PIN addr0[0]
      DIRECTION INPUT ;
      PORT
         LAYER metal3 ;
         RECT  0.0 578.2 1.2 579.4 ;
      END
   END addr0[0]
   PIN addr0[1]
      DIRECTION INPUT ;
      PORT
         LAYER metal3 ;
         RECT  0.0 600.2 1.2 601.4 ;
      END
   END addr0[1]
   PIN addr0[2]
      DIRECTION INPUT ;
      PORT
         LAYER metal3 ;
         RECT  0.0 618.2 1.2 619.4 ;
      END
   END addr0[2]
   PIN addr0[3]
      DIRECTION INPUT ;
      PORT
         LAYER metal4 ;
         RECT  343.2 981.6 344.4 982.8 ;
      END
   END addr0[3]
   PIN addr0[4]
      DIRECTION INPUT ;
      PORT
         LAYER metal4 ;
         RECT  345.8 981.6 347.0 982.8 ;
      END
   END addr0[4]
   PIN addr1[0]
      DIRECTION INPUT ;
      PORT
         LAYER metal4 ;
         RECT  3479.8 0.0 3481.0 1.2 ;
      END
   END addr1[0]
   PIN addr1[1]
      DIRECTION INPUT ;
      PORT
         LAYER metal4 ;
         RECT  3482.4 0.0 3483.6 1.2 ;
      END
   END addr1[1]
   PIN addr1[2]
      DIRECTION INPUT ;
      PORT
         LAYER metal4 ;
         RECT  3493.4 0.0 3494.6 1.2 ;
      END
   END addr1[2]
   PIN addr1[3]
      DIRECTION INPUT ;
      PORT
         LAYER metal4 ;
         RECT  3490.8 0.0 3492.0 1.2 ;
      END
   END addr1[3]
   PIN addr1[4]
      DIRECTION INPUT ;
      PORT
         LAYER metal4 ;
         RECT  3488.2 0.0 3489.4 1.2 ;
      END
   END addr1[4]
   PIN csb0
      DIRECTION INPUT ;
      PORT
         LAYER metal3 ;
         RECT  0.0 225.0 1.2 226.2 ;
      END
   END csb0
   PIN csb1
      DIRECTION INPUT ;
      PORT
         LAYER metal4 ;
         RECT  3799.0 981.6 3800.2 982.8 ;
      END
   END csb1
   PIN clk0
      DIRECTION INPUT ;
      PORT
         LAYER metal3 ;
         RECT  0.0 227.0 1.2 228.2 ;
      END
   END clk0
   PIN clk1
      DIRECTION INPUT ;
      PORT
         LAYER metal4 ;
         RECT  3752.6 981.6 3753.8 982.8 ;
      END
   END clk1
   PIN dout1[0]
      DIRECTION OUTPUT ;
      PORT
         LAYER metal4 ;
         RECT  534.7 981.6 535.9 982.8 ;
      END
   END dout1[0]
   PIN dout1[1]
      DIRECTION OUTPUT ;
      PORT
         LAYER metal4 ;
         RECT  545.5 981.6 546.7 982.8 ;
      END
   END dout1[1]
   PIN dout1[2]
      DIRECTION OUTPUT ;
      PORT
         LAYER metal4 ;
         RECT  556.3 981.6 557.5 982.8 ;
      END
   END dout1[2]
   PIN dout1[3]
      DIRECTION OUTPUT ;
      PORT
         LAYER metal4 ;
         RECT  567.1 981.6 568.3 982.8 ;
      END
   END dout1[3]
   PIN dout1[4]
      DIRECTION OUTPUT ;
      PORT
         LAYER metal4 ;
         RECT  577.9 981.6 579.1 982.8 ;
      END
   END dout1[4]
   PIN dout1[5]
      DIRECTION OUTPUT ;
      PORT
         LAYER metal4 ;
         RECT  588.7 981.6 589.9 982.8 ;
      END
   END dout1[5]
   PIN dout1[6]
      DIRECTION OUTPUT ;
      PORT
         LAYER metal4 ;
         RECT  599.5 981.6 600.7 982.8 ;
      END
   END dout1[6]
   PIN dout1[7]
      DIRECTION OUTPUT ;
      PORT
         LAYER metal4 ;
         RECT  610.3 981.6 611.5 982.8 ;
      END
   END dout1[7]
   PIN dout1[8]
      DIRECTION OUTPUT ;
      PORT
         LAYER metal4 ;
         RECT  621.1 981.6 622.3 982.8 ;
      END
   END dout1[8]
   PIN dout1[9]
      DIRECTION OUTPUT ;
      PORT
         LAYER metal4 ;
         RECT  631.9 981.6 633.1 982.8 ;
      END
   END dout1[9]
   PIN dout1[10]
      DIRECTION OUTPUT ;
      PORT
         LAYER metal4 ;
         RECT  642.7 981.6 643.9 982.8 ;
      END
   END dout1[10]
   PIN dout1[11]
      DIRECTION OUTPUT ;
      PORT
         LAYER metal4 ;
         RECT  653.5 981.6 654.7 982.8 ;
      END
   END dout1[11]
   PIN dout1[12]
      DIRECTION OUTPUT ;
      PORT
         LAYER metal4 ;
         RECT  664.3 981.6 665.5 982.8 ;
      END
   END dout1[12]
   PIN dout1[13]
      DIRECTION OUTPUT ;
      PORT
         LAYER metal4 ;
         RECT  675.1 981.6 676.3 982.8 ;
      END
   END dout1[13]
   PIN dout1[14]
      DIRECTION OUTPUT ;
      PORT
         LAYER metal4 ;
         RECT  685.9 981.6 687.1 982.8 ;
      END
   END dout1[14]
   PIN dout1[15]
      DIRECTION OUTPUT ;
      PORT
         LAYER metal4 ;
         RECT  696.7 981.6 697.9 982.8 ;
      END
   END dout1[15]
   PIN dout1[16]
      DIRECTION OUTPUT ;
      PORT
         LAYER metal4 ;
         RECT  707.5 981.6 708.7 982.8 ;
      END
   END dout1[16]
   PIN dout1[17]
      DIRECTION OUTPUT ;
      PORT
         LAYER metal4 ;
         RECT  718.3 981.6 719.5 982.8 ;
      END
   END dout1[17]
   PIN dout1[18]
      DIRECTION OUTPUT ;
      PORT
         LAYER metal4 ;
         RECT  729.1 981.6 730.3 982.8 ;
      END
   END dout1[18]
   PIN dout1[19]
      DIRECTION OUTPUT ;
      PORT
         LAYER metal4 ;
         RECT  739.9 981.6 741.1 982.8 ;
      END
   END dout1[19]
   PIN dout1[20]
      DIRECTION OUTPUT ;
      PORT
         LAYER metal4 ;
         RECT  750.7 981.6 751.9 982.8 ;
      END
   END dout1[20]
   PIN dout1[21]
      DIRECTION OUTPUT ;
      PORT
         LAYER metal4 ;
         RECT  761.5 981.6 762.7 982.8 ;
      END
   END dout1[21]
   PIN dout1[22]
      DIRECTION OUTPUT ;
      PORT
         LAYER metal4 ;
         RECT  772.3 981.6 773.5 982.8 ;
      END
   END dout1[22]
   PIN dout1[23]
      DIRECTION OUTPUT ;
      PORT
         LAYER metal4 ;
         RECT  783.1 981.6 784.3 982.8 ;
      END
   END dout1[23]
   PIN dout1[24]
      DIRECTION OUTPUT ;
      PORT
         LAYER metal4 ;
         RECT  793.9 981.6 795.1 982.8 ;
      END
   END dout1[24]
   PIN dout1[25]
      DIRECTION OUTPUT ;
      PORT
         LAYER metal4 ;
         RECT  804.7 981.6 805.9 982.8 ;
      END
   END dout1[25]
   PIN dout1[26]
      DIRECTION OUTPUT ;
      PORT
         LAYER metal4 ;
         RECT  815.5 981.6 816.7 982.8 ;
      END
   END dout1[26]
   PIN dout1[27]
      DIRECTION OUTPUT ;
      PORT
         LAYER metal4 ;
         RECT  826.3 981.6 827.5 982.8 ;
      END
   END dout1[27]
   PIN dout1[28]
      DIRECTION OUTPUT ;
      PORT
         LAYER metal4 ;
         RECT  837.1 981.6 838.3 982.8 ;
      END
   END dout1[28]
   PIN dout1[29]
      DIRECTION OUTPUT ;
      PORT
         LAYER metal4 ;
         RECT  847.9 981.6 849.1 982.8 ;
      END
   END dout1[29]
   PIN dout1[30]
      DIRECTION OUTPUT ;
      PORT
         LAYER metal4 ;
         RECT  858.7 981.6 859.9 982.8 ;
      END
   END dout1[30]
   PIN dout1[31]
      DIRECTION OUTPUT ;
      PORT
         LAYER metal4 ;
         RECT  869.5 981.6 870.7 982.8 ;
      END
   END dout1[31]
   PIN dout1[32]
      DIRECTION OUTPUT ;
      PORT
         LAYER metal4 ;
         RECT  880.3 981.6 881.5 982.8 ;
      END
   END dout1[32]
   PIN dout1[33]
      DIRECTION OUTPUT ;
      PORT
         LAYER metal4 ;
         RECT  891.1 981.6 892.3 982.8 ;
      END
   END dout1[33]
   PIN dout1[34]
      DIRECTION OUTPUT ;
      PORT
         LAYER metal4 ;
         RECT  901.9 981.6 903.1 982.8 ;
      END
   END dout1[34]
   PIN dout1[35]
      DIRECTION OUTPUT ;
      PORT
         LAYER metal4 ;
         RECT  912.7 981.6 913.9 982.8 ;
      END
   END dout1[35]
   PIN dout1[36]
      DIRECTION OUTPUT ;
      PORT
         LAYER metal4 ;
         RECT  923.5 981.6 924.7 982.8 ;
      END
   END dout1[36]
   PIN dout1[37]
      DIRECTION OUTPUT ;
      PORT
         LAYER metal4 ;
         RECT  934.3 981.6 935.5 982.8 ;
      END
   END dout1[37]
   PIN dout1[38]
      DIRECTION OUTPUT ;
      PORT
         LAYER metal4 ;
         RECT  945.1 981.6 946.3 982.8 ;
      END
   END dout1[38]
   PIN dout1[39]
      DIRECTION OUTPUT ;
      PORT
         LAYER metal4 ;
         RECT  955.9 981.6 957.1 982.8 ;
      END
   END dout1[39]
   PIN dout1[40]
      DIRECTION OUTPUT ;
      PORT
         LAYER metal4 ;
         RECT  966.7 981.6 967.9 982.8 ;
      END
   END dout1[40]
   PIN dout1[41]
      DIRECTION OUTPUT ;
      PORT
         LAYER metal4 ;
         RECT  977.5 981.6 978.7 982.8 ;
      END
   END dout1[41]
   PIN dout1[42]
      DIRECTION OUTPUT ;
      PORT
         LAYER metal4 ;
         RECT  988.3 981.6 989.5 982.8 ;
      END
   END dout1[42]
   PIN dout1[43]
      DIRECTION OUTPUT ;
      PORT
         LAYER metal4 ;
         RECT  999.1 981.6 1000.3 982.8 ;
      END
   END dout1[43]
   PIN dout1[44]
      DIRECTION OUTPUT ;
      PORT
         LAYER metal4 ;
         RECT  1009.9 981.6 1011.1 982.8 ;
      END
   END dout1[44]
   PIN dout1[45]
      DIRECTION OUTPUT ;
      PORT
         LAYER metal4 ;
         RECT  1020.7 981.6 1021.9 982.8 ;
      END
   END dout1[45]
   PIN dout1[46]
      DIRECTION OUTPUT ;
      PORT
         LAYER metal4 ;
         RECT  1031.5 981.6 1032.7 982.8 ;
      END
   END dout1[46]
   PIN dout1[47]
      DIRECTION OUTPUT ;
      PORT
         LAYER metal4 ;
         RECT  1042.3 981.6 1043.5 982.8 ;
      END
   END dout1[47]
   PIN dout1[48]
      DIRECTION OUTPUT ;
      PORT
         LAYER metal4 ;
         RECT  1053.1 981.6 1054.3 982.8 ;
      END
   END dout1[48]
   PIN dout1[49]
      DIRECTION OUTPUT ;
      PORT
         LAYER metal4 ;
         RECT  1063.9 981.6 1065.1 982.8 ;
      END
   END dout1[49]
   PIN dout1[50]
      DIRECTION OUTPUT ;
      PORT
         LAYER metal4 ;
         RECT  1074.7 981.6 1075.9 982.8 ;
      END
   END dout1[50]
   PIN dout1[51]
      DIRECTION OUTPUT ;
      PORT
         LAYER metal4 ;
         RECT  1085.5 981.6 1086.7 982.8 ;
      END
   END dout1[51]
   PIN dout1[52]
      DIRECTION OUTPUT ;
      PORT
         LAYER metal4 ;
         RECT  1096.3 981.6 1097.5 982.8 ;
      END
   END dout1[52]
   PIN dout1[53]
      DIRECTION OUTPUT ;
      PORT
         LAYER metal4 ;
         RECT  1107.1 981.6 1108.3 982.8 ;
      END
   END dout1[53]
   PIN dout1[54]
      DIRECTION OUTPUT ;
      PORT
         LAYER metal4 ;
         RECT  1117.9 981.6 1119.1 982.8 ;
      END
   END dout1[54]
   PIN dout1[55]
      DIRECTION OUTPUT ;
      PORT
         LAYER metal4 ;
         RECT  1128.7 981.6 1129.9 982.8 ;
      END
   END dout1[55]
   PIN dout1[56]
      DIRECTION OUTPUT ;
      PORT
         LAYER metal4 ;
         RECT  1139.5 981.6 1140.7 982.8 ;
      END
   END dout1[56]
   PIN dout1[57]
      DIRECTION OUTPUT ;
      PORT
         LAYER metal4 ;
         RECT  1150.3 981.6 1151.5 982.8 ;
      END
   END dout1[57]
   PIN dout1[58]
      DIRECTION OUTPUT ;
      PORT
         LAYER metal4 ;
         RECT  1161.1 981.6 1162.3 982.8 ;
      END
   END dout1[58]
   PIN dout1[59]
      DIRECTION OUTPUT ;
      PORT
         LAYER metal4 ;
         RECT  1171.9 981.6 1173.1 982.8 ;
      END
   END dout1[59]
   PIN dout1[60]
      DIRECTION OUTPUT ;
      PORT
         LAYER metal4 ;
         RECT  1182.7 981.6 1183.9 982.8 ;
      END
   END dout1[60]
   PIN dout1[61]
      DIRECTION OUTPUT ;
      PORT
         LAYER metal4 ;
         RECT  1193.5 981.6 1194.7 982.8 ;
      END
   END dout1[61]
   PIN dout1[62]
      DIRECTION OUTPUT ;
      PORT
         LAYER metal4 ;
         RECT  1204.3 981.6 1205.5 982.8 ;
      END
   END dout1[62]
   PIN dout1[63]
      DIRECTION OUTPUT ;
      PORT
         LAYER metal4 ;
         RECT  1215.1 981.6 1216.3 982.8 ;
      END
   END dout1[63]
   PIN dout1[64]
      DIRECTION OUTPUT ;
      PORT
         LAYER metal4 ;
         RECT  1225.9 981.6 1227.1 982.8 ;
      END
   END dout1[64]
   PIN dout1[65]
      DIRECTION OUTPUT ;
      PORT
         LAYER metal4 ;
         RECT  1236.7 981.6 1237.9 982.8 ;
      END
   END dout1[65]
   PIN dout1[66]
      DIRECTION OUTPUT ;
      PORT
         LAYER metal4 ;
         RECT  1247.5 981.6 1248.7 982.8 ;
      END
   END dout1[66]
   PIN dout1[67]
      DIRECTION OUTPUT ;
      PORT
         LAYER metal4 ;
         RECT  1258.3 981.6 1259.5 982.8 ;
      END
   END dout1[67]
   PIN dout1[68]
      DIRECTION OUTPUT ;
      PORT
         LAYER metal4 ;
         RECT  1269.1 981.6 1270.3 982.8 ;
      END
   END dout1[68]
   PIN dout1[69]
      DIRECTION OUTPUT ;
      PORT
         LAYER metal4 ;
         RECT  1279.9 981.6 1281.1 982.8 ;
      END
   END dout1[69]
   PIN dout1[70]
      DIRECTION OUTPUT ;
      PORT
         LAYER metal4 ;
         RECT  1290.7 981.6 1291.9 982.8 ;
      END
   END dout1[70]
   PIN dout1[71]
      DIRECTION OUTPUT ;
      PORT
         LAYER metal4 ;
         RECT  1301.5 981.6 1302.7 982.8 ;
      END
   END dout1[71]
   PIN dout1[72]
      DIRECTION OUTPUT ;
      PORT
         LAYER metal4 ;
         RECT  1312.3 981.6 1313.5 982.8 ;
      END
   END dout1[72]
   PIN dout1[73]
      DIRECTION OUTPUT ;
      PORT
         LAYER metal4 ;
         RECT  1323.1 981.6 1324.3 982.8 ;
      END
   END dout1[73]
   PIN dout1[74]
      DIRECTION OUTPUT ;
      PORT
         LAYER metal4 ;
         RECT  1333.9 981.6 1335.1 982.8 ;
      END
   END dout1[74]
   PIN dout1[75]
      DIRECTION OUTPUT ;
      PORT
         LAYER metal4 ;
         RECT  1344.7 981.6 1345.9 982.8 ;
      END
   END dout1[75]
   PIN dout1[76]
      DIRECTION OUTPUT ;
      PORT
         LAYER metal4 ;
         RECT  1355.5 981.6 1356.7 982.8 ;
      END
   END dout1[76]
   PIN dout1[77]
      DIRECTION OUTPUT ;
      PORT
         LAYER metal4 ;
         RECT  1366.3 981.6 1367.5 982.8 ;
      END
   END dout1[77]
   PIN dout1[78]
      DIRECTION OUTPUT ;
      PORT
         LAYER metal4 ;
         RECT  1377.1 981.6 1378.3 982.8 ;
      END
   END dout1[78]
   PIN dout1[79]
      DIRECTION OUTPUT ;
      PORT
         LAYER metal4 ;
         RECT  1387.9 981.6 1389.1 982.8 ;
      END
   END dout1[79]
   PIN dout1[80]
      DIRECTION OUTPUT ;
      PORT
         LAYER metal4 ;
         RECT  1398.7 981.6 1399.9 982.8 ;
      END
   END dout1[80]
   PIN dout1[81]
      DIRECTION OUTPUT ;
      PORT
         LAYER metal4 ;
         RECT  1409.5 981.6 1410.7 982.8 ;
      END
   END dout1[81]
   PIN dout1[82]
      DIRECTION OUTPUT ;
      PORT
         LAYER metal4 ;
         RECT  1420.3 981.6 1421.5 982.8 ;
      END
   END dout1[82]
   PIN dout1[83]
      DIRECTION OUTPUT ;
      PORT
         LAYER metal4 ;
         RECT  1431.1 981.6 1432.3 982.8 ;
      END
   END dout1[83]
   PIN dout1[84]
      DIRECTION OUTPUT ;
      PORT
         LAYER metal4 ;
         RECT  1441.9 981.6 1443.1 982.8 ;
      END
   END dout1[84]
   PIN dout1[85]
      DIRECTION OUTPUT ;
      PORT
         LAYER metal4 ;
         RECT  1452.7 981.6 1453.9 982.8 ;
      END
   END dout1[85]
   PIN dout1[86]
      DIRECTION OUTPUT ;
      PORT
         LAYER metal4 ;
         RECT  1463.5 981.6 1464.7 982.8 ;
      END
   END dout1[86]
   PIN dout1[87]
      DIRECTION OUTPUT ;
      PORT
         LAYER metal4 ;
         RECT  1474.3 981.6 1475.5 982.8 ;
      END
   END dout1[87]
   PIN dout1[88]
      DIRECTION OUTPUT ;
      PORT
         LAYER metal4 ;
         RECT  1485.1 981.6 1486.3 982.8 ;
      END
   END dout1[88]
   PIN dout1[89]
      DIRECTION OUTPUT ;
      PORT
         LAYER metal4 ;
         RECT  1495.9 981.6 1497.1 982.8 ;
      END
   END dout1[89]
   PIN dout1[90]
      DIRECTION OUTPUT ;
      PORT
         LAYER metal4 ;
         RECT  1506.7 981.6 1507.9 982.8 ;
      END
   END dout1[90]
   PIN dout1[91]
      DIRECTION OUTPUT ;
      PORT
         LAYER metal4 ;
         RECT  1517.5 981.6 1518.7 982.8 ;
      END
   END dout1[91]
   PIN dout1[92]
      DIRECTION OUTPUT ;
      PORT
         LAYER metal4 ;
         RECT  1528.3 981.6 1529.5 982.8 ;
      END
   END dout1[92]
   PIN dout1[93]
      DIRECTION OUTPUT ;
      PORT
         LAYER metal4 ;
         RECT  1539.1 981.6 1540.3 982.8 ;
      END
   END dout1[93]
   PIN dout1[94]
      DIRECTION OUTPUT ;
      PORT
         LAYER metal4 ;
         RECT  1549.9 981.6 1551.1 982.8 ;
      END
   END dout1[94]
   PIN dout1[95]
      DIRECTION OUTPUT ;
      PORT
         LAYER metal4 ;
         RECT  1560.7 981.6 1561.9 982.8 ;
      END
   END dout1[95]
   PIN dout1[96]
      DIRECTION OUTPUT ;
      PORT
         LAYER metal4 ;
         RECT  1571.5 981.6 1572.7 982.8 ;
      END
   END dout1[96]
   PIN dout1[97]
      DIRECTION OUTPUT ;
      PORT
         LAYER metal4 ;
         RECT  1582.3 981.6 1583.5 982.8 ;
      END
   END dout1[97]
   PIN dout1[98]
      DIRECTION OUTPUT ;
      PORT
         LAYER metal4 ;
         RECT  1593.1 981.6 1594.3 982.8 ;
      END
   END dout1[98]
   PIN dout1[99]
      DIRECTION OUTPUT ;
      PORT
         LAYER metal4 ;
         RECT  1603.9 981.6 1605.1 982.8 ;
      END
   END dout1[99]
   PIN dout1[100]
      DIRECTION OUTPUT ;
      PORT
         LAYER metal4 ;
         RECT  1614.7 981.6 1615.9 982.8 ;
      END
   END dout1[100]
   PIN dout1[101]
      DIRECTION OUTPUT ;
      PORT
         LAYER metal4 ;
         RECT  1625.5 981.6 1626.7 982.8 ;
      END
   END dout1[101]
   PIN dout1[102]
      DIRECTION OUTPUT ;
      PORT
         LAYER metal4 ;
         RECT  1636.3 981.6 1637.5 982.8 ;
      END
   END dout1[102]
   PIN dout1[103]
      DIRECTION OUTPUT ;
      PORT
         LAYER metal4 ;
         RECT  1647.1 981.6 1648.3 982.8 ;
      END
   END dout1[103]
   PIN dout1[104]
      DIRECTION OUTPUT ;
      PORT
         LAYER metal4 ;
         RECT  1657.9 981.6 1659.1 982.8 ;
      END
   END dout1[104]
   PIN dout1[105]
      DIRECTION OUTPUT ;
      PORT
         LAYER metal4 ;
         RECT  1668.7 981.6 1669.9 982.8 ;
      END
   END dout1[105]
   PIN dout1[106]
      DIRECTION OUTPUT ;
      PORT
         LAYER metal4 ;
         RECT  1679.5 981.6 1680.7 982.8 ;
      END
   END dout1[106]
   PIN dout1[107]
      DIRECTION OUTPUT ;
      PORT
         LAYER metal4 ;
         RECT  1690.3 981.6 1691.5 982.8 ;
      END
   END dout1[107]
   PIN dout1[108]
      DIRECTION OUTPUT ;
      PORT
         LAYER metal4 ;
         RECT  1701.1 981.6 1702.3 982.8 ;
      END
   END dout1[108]
   PIN dout1[109]
      DIRECTION OUTPUT ;
      PORT
         LAYER metal4 ;
         RECT  1711.9 981.6 1713.1 982.8 ;
      END
   END dout1[109]
   PIN dout1[110]
      DIRECTION OUTPUT ;
      PORT
         LAYER metal4 ;
         RECT  1722.7 981.6 1723.9 982.8 ;
      END
   END dout1[110]
   PIN dout1[111]
      DIRECTION OUTPUT ;
      PORT
         LAYER metal4 ;
         RECT  1733.5 981.6 1734.7 982.8 ;
      END
   END dout1[111]
   PIN dout1[112]
      DIRECTION OUTPUT ;
      PORT
         LAYER metal4 ;
         RECT  1744.3 981.6 1745.5 982.8 ;
      END
   END dout1[112]
   PIN dout1[113]
      DIRECTION OUTPUT ;
      PORT
         LAYER metal4 ;
         RECT  1755.1 981.6 1756.3 982.8 ;
      END
   END dout1[113]
   PIN dout1[114]
      DIRECTION OUTPUT ;
      PORT
         LAYER metal4 ;
         RECT  1765.9 981.6 1767.1 982.8 ;
      END
   END dout1[114]
   PIN dout1[115]
      DIRECTION OUTPUT ;
      PORT
         LAYER metal4 ;
         RECT  1776.7 981.6 1777.9 982.8 ;
      END
   END dout1[115]
   PIN dout1[116]
      DIRECTION OUTPUT ;
      PORT
         LAYER metal4 ;
         RECT  1787.5 981.6 1788.7 982.8 ;
      END
   END dout1[116]
   PIN dout1[117]
      DIRECTION OUTPUT ;
      PORT
         LAYER metal4 ;
         RECT  1798.3 981.6 1799.5 982.8 ;
      END
   END dout1[117]
   PIN dout1[118]
      DIRECTION OUTPUT ;
      PORT
         LAYER metal4 ;
         RECT  1809.1 981.6 1810.3 982.8 ;
      END
   END dout1[118]
   PIN dout1[119]
      DIRECTION OUTPUT ;
      PORT
         LAYER metal4 ;
         RECT  1819.9 981.6 1821.1 982.8 ;
      END
   END dout1[119]
   PIN dout1[120]
      DIRECTION OUTPUT ;
      PORT
         LAYER metal4 ;
         RECT  1830.7 981.6 1831.9 982.8 ;
      END
   END dout1[120]
   PIN dout1[121]
      DIRECTION OUTPUT ;
      PORT
         LAYER metal4 ;
         RECT  1841.5 981.6 1842.7 982.8 ;
      END
   END dout1[121]
   PIN dout1[122]
      DIRECTION OUTPUT ;
      PORT
         LAYER metal4 ;
         RECT  1852.3 981.6 1853.5 982.8 ;
      END
   END dout1[122]
   PIN dout1[123]
      DIRECTION OUTPUT ;
      PORT
         LAYER metal4 ;
         RECT  1863.1 981.6 1864.3 982.8 ;
      END
   END dout1[123]
   PIN dout1[124]
      DIRECTION OUTPUT ;
      PORT
         LAYER metal4 ;
         RECT  1873.9 981.6 1875.1 982.8 ;
      END
   END dout1[124]
   PIN dout1[125]
      DIRECTION OUTPUT ;
      PORT
         LAYER metal4 ;
         RECT  1884.7 981.6 1885.9 982.8 ;
      END
   END dout1[125]
   PIN dout1[126]
      DIRECTION OUTPUT ;
      PORT
         LAYER metal4 ;
         RECT  1895.5 981.6 1896.7 982.8 ;
      END
   END dout1[126]
   PIN dout1[127]
      DIRECTION OUTPUT ;
      PORT
         LAYER metal4 ;
         RECT  1906.3 981.6 1907.5 982.8 ;
      END
   END dout1[127]
   PIN dout1[128]
      DIRECTION OUTPUT ;
      PORT
         LAYER metal4 ;
         RECT  1917.1 981.6 1918.3 982.8 ;
      END
   END dout1[128]
   PIN dout1[129]
      DIRECTION OUTPUT ;
      PORT
         LAYER metal4 ;
         RECT  1927.9 981.6 1929.1 982.8 ;
      END
   END dout1[129]
   PIN dout1[130]
      DIRECTION OUTPUT ;
      PORT
         LAYER metal4 ;
         RECT  1938.7 981.6 1939.9 982.8 ;
      END
   END dout1[130]
   PIN dout1[131]
      DIRECTION OUTPUT ;
      PORT
         LAYER metal4 ;
         RECT  1949.5 981.6 1950.7 982.8 ;
      END
   END dout1[131]
   PIN dout1[132]
      DIRECTION OUTPUT ;
      PORT
         LAYER metal4 ;
         RECT  1960.3 981.6 1961.5 982.8 ;
      END
   END dout1[132]
   PIN dout1[133]
      DIRECTION OUTPUT ;
      PORT
         LAYER metal4 ;
         RECT  1971.1 981.6 1972.3 982.8 ;
      END
   END dout1[133]
   PIN dout1[134]
      DIRECTION OUTPUT ;
      PORT
         LAYER metal4 ;
         RECT  1981.9 981.6 1983.1 982.8 ;
      END
   END dout1[134]
   PIN dout1[135]
      DIRECTION OUTPUT ;
      PORT
         LAYER metal4 ;
         RECT  1992.7 981.6 1993.9 982.8 ;
      END
   END dout1[135]
   PIN dout1[136]
      DIRECTION OUTPUT ;
      PORT
         LAYER metal4 ;
         RECT  2003.5 981.6 2004.7 982.8 ;
      END
   END dout1[136]
   PIN dout1[137]
      DIRECTION OUTPUT ;
      PORT
         LAYER metal4 ;
         RECT  2014.3 981.6 2015.5 982.8 ;
      END
   END dout1[137]
   PIN dout1[138]
      DIRECTION OUTPUT ;
      PORT
         LAYER metal4 ;
         RECT  2025.1 981.6 2026.3 982.8 ;
      END
   END dout1[138]
   PIN dout1[139]
      DIRECTION OUTPUT ;
      PORT
         LAYER metal4 ;
         RECT  2035.9 981.6 2037.1 982.8 ;
      END
   END dout1[139]
   PIN dout1[140]
      DIRECTION OUTPUT ;
      PORT
         LAYER metal4 ;
         RECT  2046.7 981.6 2047.9 982.8 ;
      END
   END dout1[140]
   PIN dout1[141]
      DIRECTION OUTPUT ;
      PORT
         LAYER metal4 ;
         RECT  2057.5 981.6 2058.7 982.8 ;
      END
   END dout1[141]
   PIN dout1[142]
      DIRECTION OUTPUT ;
      PORT
         LAYER metal4 ;
         RECT  2068.3 981.6 2069.5 982.8 ;
      END
   END dout1[142]
   PIN dout1[143]
      DIRECTION OUTPUT ;
      PORT
         LAYER metal4 ;
         RECT  2079.1 981.6 2080.3 982.8 ;
      END
   END dout1[143]
   PIN dout1[144]
      DIRECTION OUTPUT ;
      PORT
         LAYER metal4 ;
         RECT  2089.9 981.6 2091.1 982.8 ;
      END
   END dout1[144]
   PIN dout1[145]
      DIRECTION OUTPUT ;
      PORT
         LAYER metal4 ;
         RECT  2100.7 981.6 2101.9 982.8 ;
      END
   END dout1[145]
   PIN dout1[146]
      DIRECTION OUTPUT ;
      PORT
         LAYER metal4 ;
         RECT  2111.5 981.6 2112.7 982.8 ;
      END
   END dout1[146]
   PIN dout1[147]
      DIRECTION OUTPUT ;
      PORT
         LAYER metal4 ;
         RECT  2122.3 981.6 2123.5 982.8 ;
      END
   END dout1[147]
   PIN dout1[148]
      DIRECTION OUTPUT ;
      PORT
         LAYER metal4 ;
         RECT  2133.1 981.6 2134.3 982.8 ;
      END
   END dout1[148]
   PIN dout1[149]
      DIRECTION OUTPUT ;
      PORT
         LAYER metal4 ;
         RECT  2143.9 981.6 2145.1 982.8 ;
      END
   END dout1[149]
   PIN dout1[150]
      DIRECTION OUTPUT ;
      PORT
         LAYER metal4 ;
         RECT  2154.7 981.6 2155.9 982.8 ;
      END
   END dout1[150]
   PIN dout1[151]
      DIRECTION OUTPUT ;
      PORT
         LAYER metal4 ;
         RECT  2165.5 981.6 2166.7 982.8 ;
      END
   END dout1[151]
   PIN dout1[152]
      DIRECTION OUTPUT ;
      PORT
         LAYER metal4 ;
         RECT  2176.3 981.6 2177.5 982.8 ;
      END
   END dout1[152]
   PIN dout1[153]
      DIRECTION OUTPUT ;
      PORT
         LAYER metal4 ;
         RECT  2187.1 981.6 2188.3 982.8 ;
      END
   END dout1[153]
   PIN dout1[154]
      DIRECTION OUTPUT ;
      PORT
         LAYER metal4 ;
         RECT  2197.9 981.6 2199.1 982.8 ;
      END
   END dout1[154]
   PIN dout1[155]
      DIRECTION OUTPUT ;
      PORT
         LAYER metal4 ;
         RECT  2208.7 981.6 2209.9 982.8 ;
      END
   END dout1[155]
   PIN dout1[156]
      DIRECTION OUTPUT ;
      PORT
         LAYER metal4 ;
         RECT  2219.5 981.6 2220.7 982.8 ;
      END
   END dout1[156]
   PIN dout1[157]
      DIRECTION OUTPUT ;
      PORT
         LAYER metal4 ;
         RECT  2230.3 981.6 2231.5 982.8 ;
      END
   END dout1[157]
   PIN dout1[158]
      DIRECTION OUTPUT ;
      PORT
         LAYER metal4 ;
         RECT  2241.1 981.6 2242.3 982.8 ;
      END
   END dout1[158]
   PIN dout1[159]
      DIRECTION OUTPUT ;
      PORT
         LAYER metal4 ;
         RECT  2251.9 981.6 2253.1 982.8 ;
      END
   END dout1[159]
   PIN dout1[160]
      DIRECTION OUTPUT ;
      PORT
         LAYER metal4 ;
         RECT  2262.7 981.6 2263.9 982.8 ;
      END
   END dout1[160]
   PIN dout1[161]
      DIRECTION OUTPUT ;
      PORT
         LAYER metal4 ;
         RECT  2273.5 981.6 2274.7 982.8 ;
      END
   END dout1[161]
   PIN dout1[162]
      DIRECTION OUTPUT ;
      PORT
         LAYER metal4 ;
         RECT  2284.3 981.6 2285.5 982.8 ;
      END
   END dout1[162]
   PIN dout1[163]
      DIRECTION OUTPUT ;
      PORT
         LAYER metal4 ;
         RECT  2295.1 981.6 2296.3 982.8 ;
      END
   END dout1[163]
   PIN dout1[164]
      DIRECTION OUTPUT ;
      PORT
         LAYER metal4 ;
         RECT  2305.9 981.6 2307.1 982.8 ;
      END
   END dout1[164]
   PIN dout1[165]
      DIRECTION OUTPUT ;
      PORT
         LAYER metal4 ;
         RECT  2316.7 981.6 2317.9 982.8 ;
      END
   END dout1[165]
   PIN dout1[166]
      DIRECTION OUTPUT ;
      PORT
         LAYER metal4 ;
         RECT  2327.5 981.6 2328.7 982.8 ;
      END
   END dout1[166]
   PIN dout1[167]
      DIRECTION OUTPUT ;
      PORT
         LAYER metal4 ;
         RECT  2338.3 981.6 2339.5 982.8 ;
      END
   END dout1[167]
   PIN dout1[168]
      DIRECTION OUTPUT ;
      PORT
         LAYER metal4 ;
         RECT  2349.1 981.6 2350.3 982.8 ;
      END
   END dout1[168]
   PIN dout1[169]
      DIRECTION OUTPUT ;
      PORT
         LAYER metal4 ;
         RECT  2359.9 981.6 2361.1 982.8 ;
      END
   END dout1[169]
   PIN dout1[170]
      DIRECTION OUTPUT ;
      PORT
         LAYER metal4 ;
         RECT  2370.7 981.6 2371.9 982.8 ;
      END
   END dout1[170]
   PIN dout1[171]
      DIRECTION OUTPUT ;
      PORT
         LAYER metal4 ;
         RECT  2381.5 981.6 2382.7 982.8 ;
      END
   END dout1[171]
   PIN dout1[172]
      DIRECTION OUTPUT ;
      PORT
         LAYER metal4 ;
         RECT  2392.3 981.6 2393.5 982.8 ;
      END
   END dout1[172]
   PIN dout1[173]
      DIRECTION OUTPUT ;
      PORT
         LAYER metal4 ;
         RECT  2403.1 981.6 2404.3 982.8 ;
      END
   END dout1[173]
   PIN dout1[174]
      DIRECTION OUTPUT ;
      PORT
         LAYER metal4 ;
         RECT  2413.9 981.6 2415.1 982.8 ;
      END
   END dout1[174]
   PIN dout1[175]
      DIRECTION OUTPUT ;
      PORT
         LAYER metal4 ;
         RECT  2424.7 981.6 2425.9 982.8 ;
      END
   END dout1[175]
   PIN dout1[176]
      DIRECTION OUTPUT ;
      PORT
         LAYER metal4 ;
         RECT  2435.5 981.6 2436.7 982.8 ;
      END
   END dout1[176]
   PIN dout1[177]
      DIRECTION OUTPUT ;
      PORT
         LAYER metal4 ;
         RECT  2446.3 981.6 2447.5 982.8 ;
      END
   END dout1[177]
   PIN dout1[178]
      DIRECTION OUTPUT ;
      PORT
         LAYER metal4 ;
         RECT  2457.1 981.6 2458.3 982.8 ;
      END
   END dout1[178]
   PIN dout1[179]
      DIRECTION OUTPUT ;
      PORT
         LAYER metal4 ;
         RECT  2467.9 981.6 2469.1 982.8 ;
      END
   END dout1[179]
   PIN dout1[180]
      DIRECTION OUTPUT ;
      PORT
         LAYER metal4 ;
         RECT  2478.7 981.6 2479.9 982.8 ;
      END
   END dout1[180]
   PIN dout1[181]
      DIRECTION OUTPUT ;
      PORT
         LAYER metal4 ;
         RECT  2489.5 981.6 2490.7 982.8 ;
      END
   END dout1[181]
   PIN dout1[182]
      DIRECTION OUTPUT ;
      PORT
         LAYER metal4 ;
         RECT  2500.3 981.6 2501.5 982.8 ;
      END
   END dout1[182]
   PIN dout1[183]
      DIRECTION OUTPUT ;
      PORT
         LAYER metal4 ;
         RECT  2511.1 981.6 2512.3 982.8 ;
      END
   END dout1[183]
   PIN dout1[184]
      DIRECTION OUTPUT ;
      PORT
         LAYER metal4 ;
         RECT  2521.9 981.6 2523.1 982.8 ;
      END
   END dout1[184]
   PIN dout1[185]
      DIRECTION OUTPUT ;
      PORT
         LAYER metal4 ;
         RECT  2532.7 981.6 2533.9 982.8 ;
      END
   END dout1[185]
   PIN dout1[186]
      DIRECTION OUTPUT ;
      PORT
         LAYER metal4 ;
         RECT  2543.5 981.6 2544.7 982.8 ;
      END
   END dout1[186]
   PIN dout1[187]
      DIRECTION OUTPUT ;
      PORT
         LAYER metal4 ;
         RECT  2554.3 981.6 2555.5 982.8 ;
      END
   END dout1[187]
   PIN dout1[188]
      DIRECTION OUTPUT ;
      PORT
         LAYER metal4 ;
         RECT  2565.1 981.6 2566.3 982.8 ;
      END
   END dout1[188]
   PIN dout1[189]
      DIRECTION OUTPUT ;
      PORT
         LAYER metal4 ;
         RECT  2575.9 981.6 2577.1 982.8 ;
      END
   END dout1[189]
   PIN dout1[190]
      DIRECTION OUTPUT ;
      PORT
         LAYER metal4 ;
         RECT  2586.7 981.6 2587.9 982.8 ;
      END
   END dout1[190]
   PIN dout1[191]
      DIRECTION OUTPUT ;
      PORT
         LAYER metal4 ;
         RECT  2597.5 981.6 2598.7 982.8 ;
      END
   END dout1[191]
   PIN dout1[192]
      DIRECTION OUTPUT ;
      PORT
         LAYER metal4 ;
         RECT  2608.3 981.6 2609.5 982.8 ;
      END
   END dout1[192]
   PIN dout1[193]
      DIRECTION OUTPUT ;
      PORT
         LAYER metal4 ;
         RECT  2619.1 981.6 2620.3 982.8 ;
      END
   END dout1[193]
   PIN dout1[194]
      DIRECTION OUTPUT ;
      PORT
         LAYER metal4 ;
         RECT  2629.9 981.6 2631.1 982.8 ;
      END
   END dout1[194]
   PIN dout1[195]
      DIRECTION OUTPUT ;
      PORT
         LAYER metal4 ;
         RECT  2640.7 981.6 2641.9 982.8 ;
      END
   END dout1[195]
   PIN dout1[196]
      DIRECTION OUTPUT ;
      PORT
         LAYER metal4 ;
         RECT  2651.5 981.6 2652.7 982.8 ;
      END
   END dout1[196]
   PIN dout1[197]
      DIRECTION OUTPUT ;
      PORT
         LAYER metal4 ;
         RECT  2662.3 981.6 2663.5 982.8 ;
      END
   END dout1[197]
   PIN dout1[198]
      DIRECTION OUTPUT ;
      PORT
         LAYER metal4 ;
         RECT  2673.1 981.6 2674.3 982.8 ;
      END
   END dout1[198]
   PIN dout1[199]
      DIRECTION OUTPUT ;
      PORT
         LAYER metal4 ;
         RECT  2683.9 981.6 2685.1 982.8 ;
      END
   END dout1[199]
   PIN dout1[200]
      DIRECTION OUTPUT ;
      PORT
         LAYER metal4 ;
         RECT  2694.7 981.6 2695.9 982.8 ;
      END
   END dout1[200]
   PIN dout1[201]
      DIRECTION OUTPUT ;
      PORT
         LAYER metal4 ;
         RECT  2705.5 981.6 2706.7 982.8 ;
      END
   END dout1[201]
   PIN dout1[202]
      DIRECTION OUTPUT ;
      PORT
         LAYER metal4 ;
         RECT  2716.3 981.6 2717.5 982.8 ;
      END
   END dout1[202]
   PIN dout1[203]
      DIRECTION OUTPUT ;
      PORT
         LAYER metal4 ;
         RECT  2727.1 981.6 2728.3 982.8 ;
      END
   END dout1[203]
   PIN dout1[204]
      DIRECTION OUTPUT ;
      PORT
         LAYER metal4 ;
         RECT  2737.9 981.6 2739.1 982.8 ;
      END
   END dout1[204]
   PIN dout1[205]
      DIRECTION OUTPUT ;
      PORT
         LAYER metal4 ;
         RECT  2748.7 981.6 2749.9 982.8 ;
      END
   END dout1[205]
   PIN dout1[206]
      DIRECTION OUTPUT ;
      PORT
         LAYER metal4 ;
         RECT  2759.5 981.6 2760.7 982.8 ;
      END
   END dout1[206]
   PIN dout1[207]
      DIRECTION OUTPUT ;
      PORT
         LAYER metal4 ;
         RECT  2770.3 981.6 2771.5 982.8 ;
      END
   END dout1[207]
   PIN dout1[208]
      DIRECTION OUTPUT ;
      PORT
         LAYER metal4 ;
         RECT  2781.1 981.6 2782.3 982.8 ;
      END
   END dout1[208]
   PIN dout1[209]
      DIRECTION OUTPUT ;
      PORT
         LAYER metal4 ;
         RECT  2791.9 981.6 2793.1 982.8 ;
      END
   END dout1[209]
   PIN dout1[210]
      DIRECTION OUTPUT ;
      PORT
         LAYER metal4 ;
         RECT  2802.7 981.6 2803.9 982.8 ;
      END
   END dout1[210]
   PIN dout1[211]
      DIRECTION OUTPUT ;
      PORT
         LAYER metal4 ;
         RECT  2813.5 981.6 2814.7 982.8 ;
      END
   END dout1[211]
   PIN dout1[212]
      DIRECTION OUTPUT ;
      PORT
         LAYER metal4 ;
         RECT  2824.3 981.6 2825.5 982.8 ;
      END
   END dout1[212]
   PIN dout1[213]
      DIRECTION OUTPUT ;
      PORT
         LAYER metal4 ;
         RECT  2835.1 981.6 2836.3 982.8 ;
      END
   END dout1[213]
   PIN dout1[214]
      DIRECTION OUTPUT ;
      PORT
         LAYER metal4 ;
         RECT  2845.9 981.6 2847.1 982.8 ;
      END
   END dout1[214]
   PIN dout1[215]
      DIRECTION OUTPUT ;
      PORT
         LAYER metal4 ;
         RECT  2856.7 981.6 2857.9 982.8 ;
      END
   END dout1[215]
   PIN dout1[216]
      DIRECTION OUTPUT ;
      PORT
         LAYER metal4 ;
         RECT  2867.5 981.6 2868.7 982.8 ;
      END
   END dout1[216]
   PIN dout1[217]
      DIRECTION OUTPUT ;
      PORT
         LAYER metal4 ;
         RECT  2878.3 981.6 2879.5 982.8 ;
      END
   END dout1[217]
   PIN dout1[218]
      DIRECTION OUTPUT ;
      PORT
         LAYER metal4 ;
         RECT  2889.1 981.6 2890.3 982.8 ;
      END
   END dout1[218]
   PIN dout1[219]
      DIRECTION OUTPUT ;
      PORT
         LAYER metal4 ;
         RECT  2899.9 981.6 2901.1 982.8 ;
      END
   END dout1[219]
   PIN dout1[220]
      DIRECTION OUTPUT ;
      PORT
         LAYER metal4 ;
         RECT  2910.7 981.6 2911.9 982.8 ;
      END
   END dout1[220]
   PIN dout1[221]
      DIRECTION OUTPUT ;
      PORT
         LAYER metal4 ;
         RECT  2921.5 981.6 2922.7 982.8 ;
      END
   END dout1[221]
   PIN dout1[222]
      DIRECTION OUTPUT ;
      PORT
         LAYER metal4 ;
         RECT  2932.3 981.6 2933.5 982.8 ;
      END
   END dout1[222]
   PIN dout1[223]
      DIRECTION OUTPUT ;
      PORT
         LAYER metal4 ;
         RECT  2943.1 981.6 2944.3 982.8 ;
      END
   END dout1[223]
   PIN dout1[224]
      DIRECTION OUTPUT ;
      PORT
         LAYER metal4 ;
         RECT  2953.9 981.6 2955.1 982.8 ;
      END
   END dout1[224]
   PIN dout1[225]
      DIRECTION OUTPUT ;
      PORT
         LAYER metal4 ;
         RECT  2964.7 981.6 2965.9 982.8 ;
      END
   END dout1[225]
   PIN dout1[226]
      DIRECTION OUTPUT ;
      PORT
         LAYER metal4 ;
         RECT  2975.5 981.6 2976.7 982.8 ;
      END
   END dout1[226]
   PIN dout1[227]
      DIRECTION OUTPUT ;
      PORT
         LAYER metal4 ;
         RECT  2986.3 981.6 2987.5 982.8 ;
      END
   END dout1[227]
   PIN dout1[228]
      DIRECTION OUTPUT ;
      PORT
         LAYER metal4 ;
         RECT  2997.1 981.6 2998.3 982.8 ;
      END
   END dout1[228]
   PIN dout1[229]
      DIRECTION OUTPUT ;
      PORT
         LAYER metal4 ;
         RECT  3007.9 981.6 3009.1 982.8 ;
      END
   END dout1[229]
   PIN dout1[230]
      DIRECTION OUTPUT ;
      PORT
         LAYER metal4 ;
         RECT  3018.7 981.6 3019.9 982.8 ;
      END
   END dout1[230]
   PIN dout1[231]
      DIRECTION OUTPUT ;
      PORT
         LAYER metal4 ;
         RECT  3029.5 981.6 3030.7 982.8 ;
      END
   END dout1[231]
   PIN dout1[232]
      DIRECTION OUTPUT ;
      PORT
         LAYER metal4 ;
         RECT  3040.3 981.6 3041.5 982.8 ;
      END
   END dout1[232]
   PIN dout1[233]
      DIRECTION OUTPUT ;
      PORT
         LAYER metal4 ;
         RECT  3051.1 981.6 3052.3 982.8 ;
      END
   END dout1[233]
   PIN dout1[234]
      DIRECTION OUTPUT ;
      PORT
         LAYER metal4 ;
         RECT  3061.9 981.6 3063.1 982.8 ;
      END
   END dout1[234]
   PIN dout1[235]
      DIRECTION OUTPUT ;
      PORT
         LAYER metal4 ;
         RECT  3072.7 981.6 3073.9 982.8 ;
      END
   END dout1[235]
   PIN dout1[236]
      DIRECTION OUTPUT ;
      PORT
         LAYER metal4 ;
         RECT  3083.5 981.6 3084.7 982.8 ;
      END
   END dout1[236]
   PIN dout1[237]
      DIRECTION OUTPUT ;
      PORT
         LAYER metal4 ;
         RECT  3094.3 981.6 3095.5 982.8 ;
      END
   END dout1[237]
   PIN dout1[238]
      DIRECTION OUTPUT ;
      PORT
         LAYER metal4 ;
         RECT  3105.1 981.6 3106.3 982.8 ;
      END
   END dout1[238]
   PIN dout1[239]
      DIRECTION OUTPUT ;
      PORT
         LAYER metal4 ;
         RECT  3115.9 981.6 3117.1 982.8 ;
      END
   END dout1[239]
   PIN dout1[240]
      DIRECTION OUTPUT ;
      PORT
         LAYER metal4 ;
         RECT  3126.7 981.6 3127.9 982.8 ;
      END
   END dout1[240]
   PIN dout1[241]
      DIRECTION OUTPUT ;
      PORT
         LAYER metal4 ;
         RECT  3137.5 981.6 3138.7 982.8 ;
      END
   END dout1[241]
   PIN dout1[242]
      DIRECTION OUTPUT ;
      PORT
         LAYER metal4 ;
         RECT  3148.3 981.6 3149.5 982.8 ;
      END
   END dout1[242]
   PIN dout1[243]
      DIRECTION OUTPUT ;
      PORT
         LAYER metal4 ;
         RECT  3159.1 981.6 3160.3 982.8 ;
      END
   END dout1[243]
   PIN dout1[244]
      DIRECTION OUTPUT ;
      PORT
         LAYER metal4 ;
         RECT  3169.9 981.6 3171.1 982.8 ;
      END
   END dout1[244]
   PIN dout1[245]
      DIRECTION OUTPUT ;
      PORT
         LAYER metal4 ;
         RECT  3180.7 981.6 3181.9 982.8 ;
      END
   END dout1[245]
   PIN dout1[246]
      DIRECTION OUTPUT ;
      PORT
         LAYER metal4 ;
         RECT  3191.5 981.6 3192.7 982.8 ;
      END
   END dout1[246]
   PIN dout1[247]
      DIRECTION OUTPUT ;
      PORT
         LAYER metal4 ;
         RECT  3202.3 981.6 3203.5 982.8 ;
      END
   END dout1[247]
   PIN dout1[248]
      DIRECTION OUTPUT ;
      PORT
         LAYER metal4 ;
         RECT  3213.1 981.6 3214.3 982.8 ;
      END
   END dout1[248]
   PIN dout1[249]
      DIRECTION OUTPUT ;
      PORT
         LAYER metal4 ;
         RECT  3223.9 981.6 3225.1 982.8 ;
      END
   END dout1[249]
   PIN dout1[250]
      DIRECTION OUTPUT ;
      PORT
         LAYER metal4 ;
         RECT  3234.7 981.6 3235.9 982.8 ;
      END
   END dout1[250]
   PIN dout1[251]
      DIRECTION OUTPUT ;
      PORT
         LAYER metal4 ;
         RECT  3245.5 981.6 3246.7 982.8 ;
      END
   END dout1[251]
   PIN dout1[252]
      DIRECTION OUTPUT ;
      PORT
         LAYER metal4 ;
         RECT  3256.3 981.6 3257.5 982.8 ;
      END
   END dout1[252]
   PIN dout1[253]
      DIRECTION OUTPUT ;
      PORT
         LAYER metal4 ;
         RECT  3267.1 981.6 3268.3 982.8 ;
      END
   END dout1[253]
   PIN dout1[254]
      DIRECTION OUTPUT ;
      PORT
         LAYER metal4 ;
         RECT  3277.9 981.6 3279.1 982.8 ;
      END
   END dout1[254]
   PIN dout1[255]
      DIRECTION OUTPUT ;
      PORT
         LAYER metal4 ;
         RECT  3288.7 981.6 3289.9 982.8 ;
      END
   END dout1[255]
   PIN vdd
      DIRECTION INOUT ;
      USE POWER ; 
      SHAPE ABUTMENT ; 
      PORT
         LAYER metal4 ;
         RECT  5983.2 0.0 5989.2 982.8 ;
         LAYER metal4 ;
         RECT  0.0 0.0 6.0 982.8 ;
         LAYER metal3 ;
         RECT  0.0 976.8 5989.2 982.8 ;
         LAYER metal3 ;
         RECT  0.0 0.0 5989.2 6.0 ;
      END
   END vdd
   PIN gnd
      DIRECTION INOUT ;
      USE GROUND ; 
      SHAPE ABUTMENT ; 
      PORT
         LAYER metal4 ;
         RECT  5971.2 12.0 5977.2 970.8 ;
         LAYER metal4 ;
         RECT  12.0 12.0 18.0 970.8 ;
         LAYER metal3 ;
         RECT  12.0 12.0 5977.2 18.0 ;
         LAYER metal3 ;
         RECT  12.0 964.8 5977.2 970.8 ;
      END
   END gnd
   OBS
   LAYER  metal1 ;
      RECT  1.4 1.4 5987.8 981.4 ;
   LAYER  metal2 ;
      RECT  1.4 1.4 5987.8 981.4 ;
   LAYER  metal3 ;
      RECT  2.4 577.0 5987.8 580.6 ;
      RECT  1.4 580.6 2.4 599.0 ;
      RECT  1.4 602.6 2.4 617.0 ;
      RECT  1.4 229.4 2.4 577.0 ;
      RECT  1.4 620.6 2.4 975.6 ;
      RECT  1.4 7.2 2.4 223.8 ;
      RECT  2.4 7.2 10.8 10.8 ;
      RECT  2.4 10.8 10.8 19.2 ;
      RECT  2.4 19.2 10.8 577.0 ;
      RECT  10.8 7.2 5978.4 10.8 ;
      RECT  10.8 19.2 5978.4 577.0 ;
      RECT  5978.4 7.2 5987.8 10.8 ;
      RECT  5978.4 10.8 5987.8 19.2 ;
      RECT  5978.4 19.2 5987.8 577.0 ;
      RECT  2.4 580.6 10.8 963.6 ;
      RECT  2.4 963.6 10.8 972.0 ;
      RECT  2.4 972.0 10.8 975.6 ;
      RECT  10.8 580.6 5978.4 963.6 ;
      RECT  10.8 972.0 5978.4 975.6 ;
      RECT  5978.4 580.6 5987.8 963.6 ;
      RECT  5978.4 963.6 5987.8 972.0 ;
      RECT  5978.4 972.0 5987.8 975.6 ;
   LAYER  metal4 ;
      RECT  387.0 3.6 393.0 981.4 ;
      RECT  393.0 1.4 408.8 3.6 ;
      RECT  414.8 1.4 430.6 3.6 ;
      RECT  436.6 1.4 452.4 3.6 ;
      RECT  458.4 1.4 474.2 3.6 ;
      RECT  480.2 1.4 496.0 3.6 ;
      RECT  502.0 1.4 517.8 3.6 ;
      RECT  523.8 1.4 539.6 3.6 ;
      RECT  545.6 1.4 561.4 3.6 ;
      RECT  567.4 1.4 583.2 3.6 ;
      RECT  589.2 1.4 605.0 3.6 ;
      RECT  611.0 1.4 626.8 3.6 ;
      RECT  632.8 1.4 648.6 3.6 ;
      RECT  654.6 1.4 670.4 3.6 ;
      RECT  676.4 1.4 692.2 3.6 ;
      RECT  698.2 1.4 714.0 3.6 ;
      RECT  720.0 1.4 735.8 3.6 ;
      RECT  741.8 1.4 757.6 3.6 ;
      RECT  763.6 1.4 779.4 3.6 ;
      RECT  785.4 1.4 801.2 3.6 ;
      RECT  807.2 1.4 823.0 3.6 ;
      RECT  829.0 1.4 844.8 3.6 ;
      RECT  850.8 1.4 866.6 3.6 ;
      RECT  872.6 1.4 888.4 3.6 ;
      RECT  894.4 1.4 910.2 3.6 ;
      RECT  916.2 1.4 932.0 3.6 ;
      RECT  938.0 1.4 953.8 3.6 ;
      RECT  959.8 1.4 975.6 3.6 ;
      RECT  981.6 1.4 997.4 3.6 ;
      RECT  1003.4 1.4 1019.2 3.6 ;
      RECT  1025.2 1.4 1041.0 3.6 ;
      RECT  1047.0 1.4 1062.8 3.6 ;
      RECT  1068.8 1.4 1084.6 3.6 ;
      RECT  1090.6 1.4 1106.4 3.6 ;
      RECT  1112.4 1.4 1128.2 3.6 ;
      RECT  1134.2 1.4 1150.0 3.6 ;
      RECT  1156.0 1.4 1171.8 3.6 ;
      RECT  1177.8 1.4 1193.6 3.6 ;
      RECT  1199.6 1.4 1215.4 3.6 ;
      RECT  1221.4 1.4 1237.2 3.6 ;
      RECT  1243.2 1.4 1259.0 3.6 ;
      RECT  1265.0 1.4 1280.8 3.6 ;
      RECT  1286.8 1.4 1302.6 3.6 ;
      RECT  1308.6 1.4 1324.4 3.6 ;
      RECT  1330.4 1.4 1346.2 3.6 ;
      RECT  1352.2 1.4 1368.0 3.6 ;
      RECT  1374.0 1.4 1389.8 3.6 ;
      RECT  1395.8 1.4 1411.6 3.6 ;
      RECT  1417.6 1.4 1433.4 3.6 ;
      RECT  1439.4 1.4 1455.2 3.6 ;
      RECT  1461.2 1.4 1477.0 3.6 ;
      RECT  1483.0 1.4 1498.8 3.6 ;
      RECT  1504.8 1.4 1520.6 3.6 ;
      RECT  1526.6 1.4 1542.4 3.6 ;
      RECT  1548.4 1.4 1564.2 3.6 ;
      RECT  1570.2 1.4 1586.0 3.6 ;
      RECT  1592.0 1.4 1607.8 3.6 ;
      RECT  1613.8 1.4 1629.6 3.6 ;
      RECT  1635.6 1.4 1651.4 3.6 ;
      RECT  1657.4 1.4 1673.2 3.6 ;
      RECT  1679.2 1.4 1695.0 3.6 ;
      RECT  1701.0 1.4 1716.8 3.6 ;
      RECT  1722.8 1.4 1738.6 3.6 ;
      RECT  1744.6 1.4 1760.4 3.6 ;
      RECT  1766.4 1.4 1782.2 3.6 ;
      RECT  1788.2 1.4 1804.0 3.6 ;
      RECT  1810.0 1.4 1825.8 3.6 ;
      RECT  1831.8 1.4 1847.6 3.6 ;
      RECT  1853.6 1.4 1869.4 3.6 ;
      RECT  1875.4 1.4 1891.2 3.6 ;
      RECT  1897.2 1.4 1913.0 3.6 ;
      RECT  1919.0 1.4 1934.8 3.6 ;
      RECT  1940.8 1.4 1956.6 3.6 ;
      RECT  1962.6 1.4 1978.4 3.6 ;
      RECT  1984.4 1.4 2000.2 3.6 ;
      RECT  2006.2 1.4 2022.0 3.6 ;
      RECT  2028.0 1.4 2043.8 3.6 ;
      RECT  2049.8 1.4 2065.6 3.6 ;
      RECT  2071.6 1.4 2087.4 3.6 ;
      RECT  2093.4 1.4 2109.2 3.6 ;
      RECT  2115.2 1.4 2131.0 3.6 ;
      RECT  2137.0 1.4 2152.8 3.6 ;
      RECT  2158.8 1.4 2174.6 3.6 ;
      RECT  2180.6 1.4 2196.4 3.6 ;
      RECT  2202.4 1.4 2218.2 3.6 ;
      RECT  2224.2 1.4 2240.0 3.6 ;
      RECT  2246.0 1.4 2261.8 3.6 ;
      RECT  2267.8 1.4 2283.6 3.6 ;
      RECT  2289.6 1.4 2305.4 3.6 ;
      RECT  2311.4 1.4 2327.2 3.6 ;
      RECT  2333.2 1.4 2349.0 3.6 ;
      RECT  2355.0 1.4 2370.8 3.6 ;
      RECT  2376.8 1.4 2392.6 3.6 ;
      RECT  2398.6 1.4 2414.4 3.6 ;
      RECT  2420.4 1.4 2436.2 3.6 ;
      RECT  2442.2 1.4 2458.0 3.6 ;
      RECT  2464.0 1.4 2479.8 3.6 ;
      RECT  2485.8 1.4 2501.6 3.6 ;
      RECT  2507.6 1.4 2523.4 3.6 ;
      RECT  2529.4 1.4 2545.2 3.6 ;
      RECT  2551.2 1.4 2567.0 3.6 ;
      RECT  2573.0 1.4 2588.8 3.6 ;
      RECT  2594.8 1.4 2610.6 3.6 ;
      RECT  2616.6 1.4 2632.4 3.6 ;
      RECT  2638.4 1.4 2654.2 3.6 ;
      RECT  2660.2 1.4 2676.0 3.6 ;
      RECT  2682.0 1.4 2697.8 3.6 ;
      RECT  2703.8 1.4 2719.6 3.6 ;
      RECT  2725.6 1.4 2741.4 3.6 ;
      RECT  2747.4 1.4 2763.2 3.6 ;
      RECT  2769.2 1.4 2785.0 3.6 ;
      RECT  2791.0 1.4 2806.8 3.6 ;
      RECT  2812.8 1.4 2828.6 3.6 ;
      RECT  2834.6 1.4 2850.4 3.6 ;
      RECT  2856.4 1.4 2872.2 3.6 ;
      RECT  2878.2 1.4 2894.0 3.6 ;
      RECT  2900.0 1.4 2915.8 3.6 ;
      RECT  2921.8 1.4 2937.6 3.6 ;
      RECT  2943.6 1.4 2959.4 3.6 ;
      RECT  2965.4 1.4 2981.2 3.6 ;
      RECT  2987.2 1.4 3003.0 3.6 ;
      RECT  3009.0 1.4 3024.8 3.6 ;
      RECT  3030.8 1.4 3046.6 3.6 ;
      RECT  3052.6 1.4 3068.4 3.6 ;
      RECT  3074.4 1.4 3090.2 3.6 ;
      RECT  3096.2 1.4 3112.0 3.6 ;
      RECT  3118.0 1.4 3133.8 3.6 ;
      RECT  3139.8 1.4 3155.6 3.6 ;
      RECT  3161.6 1.4 3177.4 3.6 ;
      RECT  3183.4 1.4 3199.2 3.6 ;
      RECT  3205.2 1.4 3221.0 3.6 ;
      RECT  3227.0 1.4 3242.8 3.6 ;
      RECT  3248.8 1.4 3264.6 3.6 ;
      RECT  3270.6 1.4 3286.4 3.6 ;
      RECT  3292.4 1.4 3308.2 3.6 ;
      RECT  3314.2 1.4 3330.0 3.6 ;
      RECT  3336.0 1.4 3351.8 3.6 ;
      RECT  3357.8 1.4 3373.6 3.6 ;
      RECT  3379.6 1.4 3395.4 3.6 ;
      RECT  3401.4 1.4 3417.2 3.6 ;
      RECT  3423.2 1.4 3439.0 3.6 ;
      RECT  3445.0 1.4 3460.8 3.6 ;
      RECT  3510.4 1.4 3526.2 3.6 ;
      RECT  3532.2 1.4 3548.0 3.6 ;
      RECT  3554.0 1.4 3569.8 3.6 ;
      RECT  3575.8 1.4 3591.6 3.6 ;
      RECT  3597.6 1.4 3613.4 3.6 ;
      RECT  3619.4 1.4 3635.2 3.6 ;
      RECT  3641.2 1.4 3657.0 3.6 ;
      RECT  3663.0 1.4 3678.8 3.6 ;
      RECT  3684.8 1.4 3700.6 3.6 ;
      RECT  3706.6 1.4 3722.4 3.6 ;
      RECT  3728.4 1.4 3744.2 3.6 ;
      RECT  3750.2 1.4 3766.0 3.6 ;
      RECT  3772.0 1.4 3787.8 3.6 ;
      RECT  3793.8 1.4 3809.6 3.6 ;
      RECT  3815.6 1.4 3831.4 3.6 ;
      RECT  3837.4 1.4 3853.2 3.6 ;
      RECT  3859.2 1.4 3875.0 3.6 ;
      RECT  3881.0 1.4 3896.8 3.6 ;
      RECT  3902.8 1.4 3918.6 3.6 ;
      RECT  3924.6 1.4 3940.4 3.6 ;
      RECT  3946.4 1.4 3962.2 3.6 ;
      RECT  3968.2 1.4 3984.0 3.6 ;
      RECT  3990.0 1.4 4005.8 3.6 ;
      RECT  4011.8 1.4 4027.6 3.6 ;
      RECT  4033.6 1.4 4049.4 3.6 ;
      RECT  4055.4 1.4 4071.2 3.6 ;
      RECT  4077.2 1.4 4093.0 3.6 ;
      RECT  4099.0 1.4 4114.8 3.6 ;
      RECT  4120.8 1.4 4136.6 3.6 ;
      RECT  4142.6 1.4 4158.4 3.6 ;
      RECT  4164.4 1.4 4180.2 3.6 ;
      RECT  4186.2 1.4 4202.0 3.6 ;
      RECT  4208.0 1.4 4223.8 3.6 ;
      RECT  4229.8 1.4 4245.6 3.6 ;
      RECT  4251.6 1.4 4267.4 3.6 ;
      RECT  4273.4 1.4 4289.2 3.6 ;
      RECT  4295.2 1.4 4311.0 3.6 ;
      RECT  4317.0 1.4 4332.8 3.6 ;
      RECT  4338.8 1.4 4354.6 3.6 ;
      RECT  4360.6 1.4 4376.4 3.6 ;
      RECT  4382.4 1.4 4398.2 3.6 ;
      RECT  4404.2 1.4 4420.0 3.6 ;
      RECT  4426.0 1.4 4441.8 3.6 ;
      RECT  4447.8 1.4 4463.6 3.6 ;
      RECT  4469.6 1.4 4485.4 3.6 ;
      RECT  4491.4 1.4 4507.2 3.6 ;
      RECT  4513.2 1.4 4529.0 3.6 ;
      RECT  4535.0 1.4 4550.8 3.6 ;
      RECT  4556.8 1.4 4572.6 3.6 ;
      RECT  4578.6 1.4 4594.4 3.6 ;
      RECT  4600.4 1.4 4616.2 3.6 ;
      RECT  4622.2 1.4 4638.0 3.6 ;
      RECT  4644.0 1.4 4659.8 3.6 ;
      RECT  4665.8 1.4 4681.6 3.6 ;
      RECT  4687.6 1.4 4703.4 3.6 ;
      RECT  4709.4 1.4 4725.2 3.6 ;
      RECT  4731.2 1.4 4747.0 3.6 ;
      RECT  4753.0 1.4 4768.8 3.6 ;
      RECT  4774.8 1.4 4790.6 3.6 ;
      RECT  4796.6 1.4 4812.4 3.6 ;
      RECT  4818.4 1.4 4834.2 3.6 ;
      RECT  4840.2 1.4 4856.0 3.6 ;
      RECT  4862.0 1.4 4877.8 3.6 ;
      RECT  4883.8 1.4 4899.6 3.6 ;
      RECT  4905.6 1.4 4921.4 3.6 ;
      RECT  4927.4 1.4 4943.2 3.6 ;
      RECT  4949.2 1.4 4965.0 3.6 ;
      RECT  4971.0 1.4 4986.8 3.6 ;
      RECT  4992.8 1.4 5008.6 3.6 ;
      RECT  5014.6 1.4 5030.4 3.6 ;
      RECT  5036.4 1.4 5052.2 3.6 ;
      RECT  5058.2 1.4 5074.0 3.6 ;
      RECT  5080.0 1.4 5095.8 3.6 ;
      RECT  5101.8 1.4 5117.6 3.6 ;
      RECT  5123.6 1.4 5139.4 3.6 ;
      RECT  5145.4 1.4 5161.2 3.6 ;
      RECT  5167.2 1.4 5183.0 3.6 ;
      RECT  5189.0 1.4 5204.8 3.6 ;
      RECT  5210.8 1.4 5226.6 3.6 ;
      RECT  5232.6 1.4 5248.4 3.6 ;
      RECT  5254.4 1.4 5270.2 3.6 ;
      RECT  5276.2 1.4 5292.0 3.6 ;
      RECT  5298.0 1.4 5313.8 3.6 ;
      RECT  5319.8 1.4 5335.6 3.6 ;
      RECT  5341.6 1.4 5357.4 3.6 ;
      RECT  5363.4 1.4 5379.2 3.6 ;
      RECT  5385.2 1.4 5401.0 3.6 ;
      RECT  5407.0 1.4 5422.8 3.6 ;
      RECT  5428.8 1.4 5444.6 3.6 ;
      RECT  5450.6 1.4 5466.4 3.6 ;
      RECT  5472.4 1.4 5488.2 3.6 ;
      RECT  5494.2 1.4 5510.0 3.6 ;
      RECT  5516.0 1.4 5531.8 3.6 ;
      RECT  5537.8 1.4 5553.6 3.6 ;
      RECT  5559.6 1.4 5575.4 3.6 ;
      RECT  5581.4 1.4 5597.2 3.6 ;
      RECT  5603.2 1.4 5619.0 3.6 ;
      RECT  5625.0 1.4 5640.8 3.6 ;
      RECT  5646.8 1.4 5662.6 3.6 ;
      RECT  5668.6 1.4 5684.4 3.6 ;
      RECT  5690.4 1.4 5706.2 3.6 ;
      RECT  5712.2 1.4 5728.0 3.6 ;
      RECT  5734.0 1.4 5749.8 3.6 ;
      RECT  5755.8 1.4 5771.6 3.6 ;
      RECT  5777.6 1.4 5793.4 3.6 ;
      RECT  5799.4 1.4 5815.2 3.6 ;
      RECT  5821.2 1.4 5837.0 3.6 ;
      RECT  5843.0 1.4 5858.8 3.6 ;
      RECT  5864.8 1.4 5880.6 3.6 ;
      RECT  5886.6 1.4 5902.4 3.6 ;
      RECT  5908.4 1.4 5924.2 3.6 ;
      RECT  5930.2 1.4 5946.0 3.6 ;
      RECT  340.8 3.6 346.8 979.2 ;
      RECT  346.8 3.6 387.0 979.2 ;
      RECT  349.4 979.2 387.0 981.4 ;
      RECT  3466.8 1.4 3477.4 3.6 ;
      RECT  3497.0 1.4 3504.4 3.6 ;
      RECT  393.0 3.6 3796.6 979.2 ;
      RECT  3796.6 3.6 3802.6 979.2 ;
      RECT  3756.2 979.2 3796.6 981.4 ;
      RECT  393.0 979.2 532.3 981.4 ;
      RECT  538.3 979.2 543.1 981.4 ;
      RECT  549.1 979.2 553.9 981.4 ;
      RECT  559.9 979.2 564.7 981.4 ;
      RECT  570.7 979.2 575.5 981.4 ;
      RECT  581.5 979.2 586.3 981.4 ;
      RECT  592.3 979.2 597.1 981.4 ;
      RECT  603.1 979.2 607.9 981.4 ;
      RECT  613.9 979.2 618.7 981.4 ;
      RECT  624.7 979.2 629.5 981.4 ;
      RECT  635.5 979.2 640.3 981.4 ;
      RECT  646.3 979.2 651.1 981.4 ;
      RECT  657.1 979.2 661.9 981.4 ;
      RECT  667.9 979.2 672.7 981.4 ;
      RECT  678.7 979.2 683.5 981.4 ;
      RECT  689.5 979.2 694.3 981.4 ;
      RECT  700.3 979.2 705.1 981.4 ;
      RECT  711.1 979.2 715.9 981.4 ;
      RECT  721.9 979.2 726.7 981.4 ;
      RECT  732.7 979.2 737.5 981.4 ;
      RECT  743.5 979.2 748.3 981.4 ;
      RECT  754.3 979.2 759.1 981.4 ;
      RECT  765.1 979.2 769.9 981.4 ;
      RECT  775.9 979.2 780.7 981.4 ;
      RECT  786.7 979.2 791.5 981.4 ;
      RECT  797.5 979.2 802.3 981.4 ;
      RECT  808.3 979.2 813.1 981.4 ;
      RECT  819.1 979.2 823.9 981.4 ;
      RECT  829.9 979.2 834.7 981.4 ;
      RECT  840.7 979.2 845.5 981.4 ;
      RECT  851.5 979.2 856.3 981.4 ;
      RECT  862.3 979.2 867.1 981.4 ;
      RECT  873.1 979.2 877.9 981.4 ;
      RECT  883.9 979.2 888.7 981.4 ;
      RECT  894.7 979.2 899.5 981.4 ;
      RECT  905.5 979.2 910.3 981.4 ;
      RECT  916.3 979.2 921.1 981.4 ;
      RECT  927.1 979.2 931.9 981.4 ;
      RECT  937.9 979.2 942.7 981.4 ;
      RECT  948.7 979.2 953.5 981.4 ;
      RECT  959.5 979.2 964.3 981.4 ;
      RECT  970.3 979.2 975.1 981.4 ;
      RECT  981.1 979.2 985.9 981.4 ;
      RECT  991.9 979.2 996.7 981.4 ;
      RECT  1002.7 979.2 1007.5 981.4 ;
      RECT  1013.5 979.2 1018.3 981.4 ;
      RECT  1024.3 979.2 1029.1 981.4 ;
      RECT  1035.1 979.2 1039.9 981.4 ;
      RECT  1045.9 979.2 1050.7 981.4 ;
      RECT  1056.7 979.2 1061.5 981.4 ;
      RECT  1067.5 979.2 1072.3 981.4 ;
      RECT  1078.3 979.2 1083.1 981.4 ;
      RECT  1089.1 979.2 1093.9 981.4 ;
      RECT  1099.9 979.2 1104.7 981.4 ;
      RECT  1110.7 979.2 1115.5 981.4 ;
      RECT  1121.5 979.2 1126.3 981.4 ;
      RECT  1132.3 979.2 1137.1 981.4 ;
      RECT  1143.1 979.2 1147.9 981.4 ;
      RECT  1153.9 979.2 1158.7 981.4 ;
      RECT  1164.7 979.2 1169.5 981.4 ;
      RECT  1175.5 979.2 1180.3 981.4 ;
      RECT  1186.3 979.2 1191.1 981.4 ;
      RECT  1197.1 979.2 1201.9 981.4 ;
      RECT  1207.9 979.2 1212.7 981.4 ;
      RECT  1218.7 979.2 1223.5 981.4 ;
      RECT  1229.5 979.2 1234.3 981.4 ;
      RECT  1240.3 979.2 1245.1 981.4 ;
      RECT  1251.1 979.2 1255.9 981.4 ;
      RECT  1261.9 979.2 1266.7 981.4 ;
      RECT  1272.7 979.2 1277.5 981.4 ;
      RECT  1283.5 979.2 1288.3 981.4 ;
      RECT  1294.3 979.2 1299.1 981.4 ;
      RECT  1305.1 979.2 1309.9 981.4 ;
      RECT  1315.9 979.2 1320.7 981.4 ;
      RECT  1326.7 979.2 1331.5 981.4 ;
      RECT  1337.5 979.2 1342.3 981.4 ;
      RECT  1348.3 979.2 1353.1 981.4 ;
      RECT  1359.1 979.2 1363.9 981.4 ;
      RECT  1369.9 979.2 1374.7 981.4 ;
      RECT  1380.7 979.2 1385.5 981.4 ;
      RECT  1391.5 979.2 1396.3 981.4 ;
      RECT  1402.3 979.2 1407.1 981.4 ;
      RECT  1413.1 979.2 1417.9 981.4 ;
      RECT  1423.9 979.2 1428.7 981.4 ;
      RECT  1434.7 979.2 1439.5 981.4 ;
      RECT  1445.5 979.2 1450.3 981.4 ;
      RECT  1456.3 979.2 1461.1 981.4 ;
      RECT  1467.1 979.2 1471.9 981.4 ;
      RECT  1477.9 979.2 1482.7 981.4 ;
      RECT  1488.7 979.2 1493.5 981.4 ;
      RECT  1499.5 979.2 1504.3 981.4 ;
      RECT  1510.3 979.2 1515.1 981.4 ;
      RECT  1521.1 979.2 1525.9 981.4 ;
      RECT  1531.9 979.2 1536.7 981.4 ;
      RECT  1542.7 979.2 1547.5 981.4 ;
      RECT  1553.5 979.2 1558.3 981.4 ;
      RECT  1564.3 979.2 1569.1 981.4 ;
      RECT  1575.1 979.2 1579.9 981.4 ;
      RECT  1585.9 979.2 1590.7 981.4 ;
      RECT  1596.7 979.2 1601.5 981.4 ;
      RECT  1607.5 979.2 1612.3 981.4 ;
      RECT  1618.3 979.2 1623.1 981.4 ;
      RECT  1629.1 979.2 1633.9 981.4 ;
      RECT  1639.9 979.2 1644.7 981.4 ;
      RECT  1650.7 979.2 1655.5 981.4 ;
      RECT  1661.5 979.2 1666.3 981.4 ;
      RECT  1672.3 979.2 1677.1 981.4 ;
      RECT  1683.1 979.2 1687.9 981.4 ;
      RECT  1693.9 979.2 1698.7 981.4 ;
      RECT  1704.7 979.2 1709.5 981.4 ;
      RECT  1715.5 979.2 1720.3 981.4 ;
      RECT  1726.3 979.2 1731.1 981.4 ;
      RECT  1737.1 979.2 1741.9 981.4 ;
      RECT  1747.9 979.2 1752.7 981.4 ;
      RECT  1758.7 979.2 1763.5 981.4 ;
      RECT  1769.5 979.2 1774.3 981.4 ;
      RECT  1780.3 979.2 1785.1 981.4 ;
      RECT  1791.1 979.2 1795.9 981.4 ;
      RECT  1801.9 979.2 1806.7 981.4 ;
      RECT  1812.7 979.2 1817.5 981.4 ;
      RECT  1823.5 979.2 1828.3 981.4 ;
      RECT  1834.3 979.2 1839.1 981.4 ;
      RECT  1845.1 979.2 1849.9 981.4 ;
      RECT  1855.9 979.2 1860.7 981.4 ;
      RECT  1866.7 979.2 1871.5 981.4 ;
      RECT  1877.5 979.2 1882.3 981.4 ;
      RECT  1888.3 979.2 1893.1 981.4 ;
      RECT  1899.1 979.2 1903.9 981.4 ;
      RECT  1909.9 979.2 1914.7 981.4 ;
      RECT  1920.7 979.2 1925.5 981.4 ;
      RECT  1931.5 979.2 1936.3 981.4 ;
      RECT  1942.3 979.2 1947.1 981.4 ;
      RECT  1953.1 979.2 1957.9 981.4 ;
      RECT  1963.9 979.2 1968.7 981.4 ;
      RECT  1974.7 979.2 1979.5 981.4 ;
      RECT  1985.5 979.2 1990.3 981.4 ;
      RECT  1996.3 979.2 2001.1 981.4 ;
      RECT  2007.1 979.2 2011.9 981.4 ;
      RECT  2017.9 979.2 2022.7 981.4 ;
      RECT  2028.7 979.2 2033.5 981.4 ;
      RECT  2039.5 979.2 2044.3 981.4 ;
      RECT  2050.3 979.2 2055.1 981.4 ;
      RECT  2061.1 979.2 2065.9 981.4 ;
      RECT  2071.9 979.2 2076.7 981.4 ;
      RECT  2082.7 979.2 2087.5 981.4 ;
      RECT  2093.5 979.2 2098.3 981.4 ;
      RECT  2104.3 979.2 2109.1 981.4 ;
      RECT  2115.1 979.2 2119.9 981.4 ;
      RECT  2125.9 979.2 2130.7 981.4 ;
      RECT  2136.7 979.2 2141.5 981.4 ;
      RECT  2147.5 979.2 2152.3 981.4 ;
      RECT  2158.3 979.2 2163.1 981.4 ;
      RECT  2169.1 979.2 2173.9 981.4 ;
      RECT  2179.9 979.2 2184.7 981.4 ;
      RECT  2190.7 979.2 2195.5 981.4 ;
      RECT  2201.5 979.2 2206.3 981.4 ;
      RECT  2212.3 979.2 2217.1 981.4 ;
      RECT  2223.1 979.2 2227.9 981.4 ;
      RECT  2233.9 979.2 2238.7 981.4 ;
      RECT  2244.7 979.2 2249.5 981.4 ;
      RECT  2255.5 979.2 2260.3 981.4 ;
      RECT  2266.3 979.2 2271.1 981.4 ;
      RECT  2277.1 979.2 2281.9 981.4 ;
      RECT  2287.9 979.2 2292.7 981.4 ;
      RECT  2298.7 979.2 2303.5 981.4 ;
      RECT  2309.5 979.2 2314.3 981.4 ;
      RECT  2320.3 979.2 2325.1 981.4 ;
      RECT  2331.1 979.2 2335.9 981.4 ;
      RECT  2341.9 979.2 2346.7 981.4 ;
      RECT  2352.7 979.2 2357.5 981.4 ;
      RECT  2363.5 979.2 2368.3 981.4 ;
      RECT  2374.3 979.2 2379.1 981.4 ;
      RECT  2385.1 979.2 2389.9 981.4 ;
      RECT  2395.9 979.2 2400.7 981.4 ;
      RECT  2406.7 979.2 2411.5 981.4 ;
      RECT  2417.5 979.2 2422.3 981.4 ;
      RECT  2428.3 979.2 2433.1 981.4 ;
      RECT  2439.1 979.2 2443.9 981.4 ;
      RECT  2449.9 979.2 2454.7 981.4 ;
      RECT  2460.7 979.2 2465.5 981.4 ;
      RECT  2471.5 979.2 2476.3 981.4 ;
      RECT  2482.3 979.2 2487.1 981.4 ;
      RECT  2493.1 979.2 2497.9 981.4 ;
      RECT  2503.9 979.2 2508.7 981.4 ;
      RECT  2514.7 979.2 2519.5 981.4 ;
      RECT  2525.5 979.2 2530.3 981.4 ;
      RECT  2536.3 979.2 2541.1 981.4 ;
      RECT  2547.1 979.2 2551.9 981.4 ;
      RECT  2557.9 979.2 2562.7 981.4 ;
      RECT  2568.7 979.2 2573.5 981.4 ;
      RECT  2579.5 979.2 2584.3 981.4 ;
      RECT  2590.3 979.2 2595.1 981.4 ;
      RECT  2601.1 979.2 2605.9 981.4 ;
      RECT  2611.9 979.2 2616.7 981.4 ;
      RECT  2622.7 979.2 2627.5 981.4 ;
      RECT  2633.5 979.2 2638.3 981.4 ;
      RECT  2644.3 979.2 2649.1 981.4 ;
      RECT  2655.1 979.2 2659.9 981.4 ;
      RECT  2665.9 979.2 2670.7 981.4 ;
      RECT  2676.7 979.2 2681.5 981.4 ;
      RECT  2687.5 979.2 2692.3 981.4 ;
      RECT  2698.3 979.2 2703.1 981.4 ;
      RECT  2709.1 979.2 2713.9 981.4 ;
      RECT  2719.9 979.2 2724.7 981.4 ;
      RECT  2730.7 979.2 2735.5 981.4 ;
      RECT  2741.5 979.2 2746.3 981.4 ;
      RECT  2752.3 979.2 2757.1 981.4 ;
      RECT  2763.1 979.2 2767.9 981.4 ;
      RECT  2773.9 979.2 2778.7 981.4 ;
      RECT  2784.7 979.2 2789.5 981.4 ;
      RECT  2795.5 979.2 2800.3 981.4 ;
      RECT  2806.3 979.2 2811.1 981.4 ;
      RECT  2817.1 979.2 2821.9 981.4 ;
      RECT  2827.9 979.2 2832.7 981.4 ;
      RECT  2838.7 979.2 2843.5 981.4 ;
      RECT  2849.5 979.2 2854.3 981.4 ;
      RECT  2860.3 979.2 2865.1 981.4 ;
      RECT  2871.1 979.2 2875.9 981.4 ;
      RECT  2881.9 979.2 2886.7 981.4 ;
      RECT  2892.7 979.2 2897.5 981.4 ;
      RECT  2903.5 979.2 2908.3 981.4 ;
      RECT  2914.3 979.2 2919.1 981.4 ;
      RECT  2925.1 979.2 2929.9 981.4 ;
      RECT  2935.9 979.2 2940.7 981.4 ;
      RECT  2946.7 979.2 2951.5 981.4 ;
      RECT  2957.5 979.2 2962.3 981.4 ;
      RECT  2968.3 979.2 2973.1 981.4 ;
      RECT  2979.1 979.2 2983.9 981.4 ;
      RECT  2989.9 979.2 2994.7 981.4 ;
      RECT  3000.7 979.2 3005.5 981.4 ;
      RECT  3011.5 979.2 3016.3 981.4 ;
      RECT  3022.3 979.2 3027.1 981.4 ;
      RECT  3033.1 979.2 3037.9 981.4 ;
      RECT  3043.9 979.2 3048.7 981.4 ;
      RECT  3054.7 979.2 3059.5 981.4 ;
      RECT  3065.5 979.2 3070.3 981.4 ;
      RECT  3076.3 979.2 3081.1 981.4 ;
      RECT  3087.1 979.2 3091.9 981.4 ;
      RECT  3097.9 979.2 3102.7 981.4 ;
      RECT  3108.7 979.2 3113.5 981.4 ;
      RECT  3119.5 979.2 3124.3 981.4 ;
      RECT  3130.3 979.2 3135.1 981.4 ;
      RECT  3141.1 979.2 3145.9 981.4 ;
      RECT  3151.9 979.2 3156.7 981.4 ;
      RECT  3162.7 979.2 3167.5 981.4 ;
      RECT  3173.5 979.2 3178.3 981.4 ;
      RECT  3184.3 979.2 3189.1 981.4 ;
      RECT  3195.1 979.2 3199.9 981.4 ;
      RECT  3205.9 979.2 3210.7 981.4 ;
      RECT  3216.7 979.2 3221.5 981.4 ;
      RECT  3227.5 979.2 3232.3 981.4 ;
      RECT  3238.3 979.2 3243.1 981.4 ;
      RECT  3249.1 979.2 3253.9 981.4 ;
      RECT  3259.9 979.2 3264.7 981.4 ;
      RECT  3270.7 979.2 3275.5 981.4 ;
      RECT  3281.5 979.2 3286.3 981.4 ;
      RECT  3292.3 979.2 3750.2 981.4 ;
      RECT  5952.0 1.4 5980.8 3.6 ;
      RECT  3802.6 979.2 5980.8 981.4 ;
      RECT  8.4 1.4 387.0 3.6 ;
      RECT  8.4 979.2 340.8 981.4 ;
      RECT  3802.6 3.6 5968.8 9.6 ;
      RECT  3802.6 9.6 5968.8 973.2 ;
      RECT  3802.6 973.2 5968.8 979.2 ;
      RECT  5968.8 3.6 5979.6 9.6 ;
      RECT  5968.8 973.2 5979.6 979.2 ;
      RECT  5979.6 3.6 5980.8 9.6 ;
      RECT  5979.6 9.6 5980.8 973.2 ;
      RECT  5979.6 973.2 5980.8 979.2 ;
      RECT  8.4 3.6 9.6 9.6 ;
      RECT  8.4 9.6 9.6 973.2 ;
      RECT  8.4 973.2 9.6 979.2 ;
      RECT  9.6 3.6 20.4 9.6 ;
      RECT  9.6 973.2 20.4 979.2 ;
      RECT  20.4 3.6 340.8 9.6 ;
      RECT  20.4 9.6 340.8 973.2 ;
      RECT  20.4 973.2 340.8 979.2 ;
   END
END    l2_data_array
END    LIBRARY
